VERSION 5.8 ;
BUSBITCHARS "[]" ;
DIVIDERCHAR "/" ;
UNITS
    DATABASE MICRONS 1000 ;
END UNITS

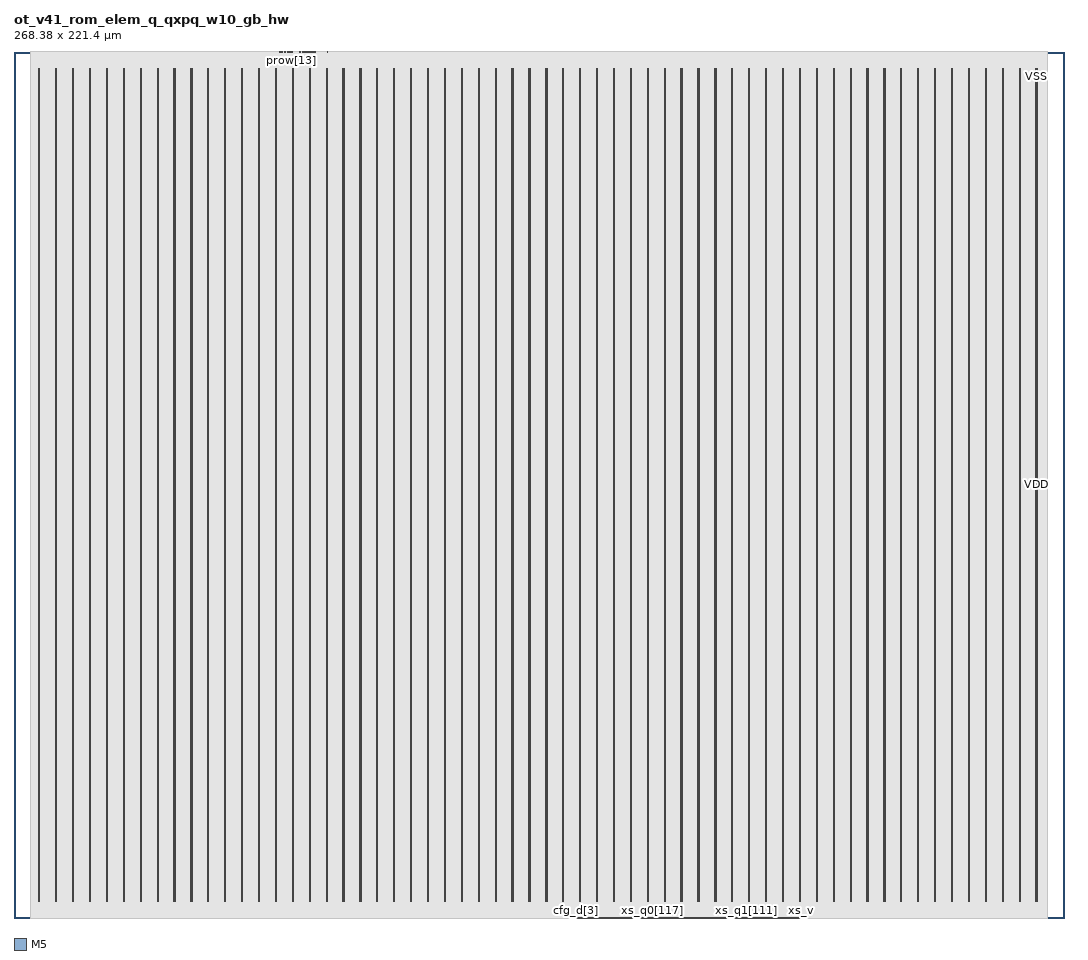
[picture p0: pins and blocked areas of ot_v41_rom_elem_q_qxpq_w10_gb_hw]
MACRO ot_v41_rom_elem_q_qxpq_w10_gb_hw
  FOREIGN ot_v41_rom_elem_q_qxpq_w10_gb_hw 0 0 ;
  CLASS BLOCK ;
  SIZE 268.38 BY 221.4 ;
  PIN bank_free
    DIRECTION OUTPUT ;
    USE SIGNAL ;
    PORT
      LAYER M5 ;
        RECT  142.752 0 142.776 0.084 ;
    END
  END bank_free
  PIN busy
    DIRECTION OUTPUT ;
    USE SIGNAL ;
    PORT
      LAYER M5 ;
        RECT  67.872 221.316 67.896 221.4 ;
    END
  END busy
  PIN cfg_a[0]
    DIRECTION INPUT ;
    USE SIGNAL ;
    PORT
      LAYER M5 ;
        RECT  142.848 0 142.872 0.084 ;
    END
  END cfg_a[0]
  PIN cfg_a[1]
    DIRECTION INPUT ;
    USE SIGNAL ;
    PORT
      LAYER M5 ;
        RECT  142.944 0 142.968 0.084 ;
    END
  END cfg_a[1]
  PIN cfg_a[2]
    DIRECTION INPUT ;
    USE SIGNAL ;
    PORT
      LAYER M5 ;
        RECT  143.04 0 143.064 0.084 ;
    END
  END cfg_a[2]
  PIN cfg_a[3]
    DIRECTION INPUT ;
    USE SIGNAL ;
    PORT
      LAYER M5 ;
        RECT  143.136 0 143.16 0.084 ;
    END
  END cfg_a[3]
  PIN cfg_a[4]
    DIRECTION INPUT ;
    USE SIGNAL ;
    PORT
      LAYER M5 ;
        RECT  143.232 0 143.256 0.084 ;
    END
  END cfg_a[4]
  PIN cfg_d[0]
    DIRECTION INPUT ;
    USE SIGNAL ;
    PORT
      LAYER M5 ;
        RECT  143.328 0 143.352 0.084 ;
    END
  END cfg_d[0]
  PIN cfg_d[10]
    DIRECTION INPUT ;
    USE SIGNAL ;
    PORT
      LAYER M5 ;
        RECT  144.288 0 144.312 0.084 ;
    END
  END cfg_d[10]
  PIN cfg_d[11]
    DIRECTION INPUT ;
    USE SIGNAL ;
    PORT
      LAYER M5 ;
        RECT  144.384 0 144.408 0.084 ;
    END
  END cfg_d[11]
  PIN cfg_d[12]
    DIRECTION INPUT ;
    USE SIGNAL ;
    PORT
      LAYER M5 ;
        RECT  144.48 0 144.504 0.084 ;
    END
  END cfg_d[12]
  PIN cfg_d[13]
    DIRECTION INPUT ;
    USE SIGNAL ;
    PORT
      LAYER M5 ;
        RECT  144.576 0 144.6 0.084 ;
    END
  END cfg_d[13]
  PIN cfg_d[14]
    DIRECTION INPUT ;
    USE SIGNAL ;
    PORT
      LAYER M5 ;
        RECT  144.672 0 144.696 0.084 ;
    END
  END cfg_d[14]
  PIN cfg_d[15]
    DIRECTION INPUT ;
    USE SIGNAL ;
    PORT
      LAYER M5 ;
        RECT  144.768 0 144.792 0.084 ;
    END
  END cfg_d[15]
  PIN cfg_d[16]
    DIRECTION INPUT ;
    USE SIGNAL ;
    PORT
      LAYER M5 ;
        RECT  144.864 0 144.888 0.084 ;
    END
  END cfg_d[16]
  PIN cfg_d[17]
    DIRECTION INPUT ;
    USE SIGNAL ;
    PORT
      LAYER M5 ;
        RECT  144.96 0 144.984 0.084 ;
    END
  END cfg_d[17]
  PIN cfg_d[18]
    DIRECTION INPUT ;
    USE SIGNAL ;
    PORT
      LAYER M5 ;
        RECT  145.056 0 145.08 0.084 ;
    END
  END cfg_d[18]
  PIN cfg_d[19]
    DIRECTION INPUT ;
    USE SIGNAL ;
    PORT
      LAYER M5 ;
        RECT  145.152 0 145.176 0.084 ;
    END
  END cfg_d[19]
  PIN cfg_d[1]
    DIRECTION INPUT ;
    USE SIGNAL ;
    PORT
      LAYER M5 ;
        RECT  143.424 0 143.448 0.084 ;
    END
  END cfg_d[1]
  PIN cfg_d[20]
    DIRECTION INPUT ;
    USE SIGNAL ;
    PORT
      LAYER M5 ;
        RECT  145.248 0 145.272 0.084 ;
    END
  END cfg_d[20]
  PIN cfg_d[21]
    DIRECTION INPUT ;
    USE SIGNAL ;
    PORT
      LAYER M5 ;
        RECT  145.344 0 145.368 0.084 ;
    END
  END cfg_d[21]
  PIN cfg_d[22]
    DIRECTION INPUT ;
    USE SIGNAL ;
    PORT
      LAYER M5 ;
        RECT  145.44 0 145.464 0.084 ;
    END
  END cfg_d[22]
  PIN cfg_d[23]
    DIRECTION INPUT ;
    USE SIGNAL ;
    PORT
      LAYER M5 ;
        RECT  145.536 0 145.56 0.084 ;
    END
  END cfg_d[23]
  PIN cfg_d[24]
    DIRECTION INPUT ;
    USE SIGNAL ;
    PORT
      LAYER M5 ;
        RECT  145.632 0 145.656 0.084 ;
    END
  END cfg_d[24]
  PIN cfg_d[25]
    DIRECTION INPUT ;
    USE SIGNAL ;
    PORT
      LAYER M5 ;
        RECT  145.728 0 145.752 0.084 ;
    END
  END cfg_d[25]
  PIN cfg_d[26]
    DIRECTION INPUT ;
    USE SIGNAL ;
    PORT
      LAYER M5 ;
        RECT  145.824 0 145.848 0.084 ;
    END
  END cfg_d[26]
  PIN cfg_d[27]
    DIRECTION INPUT ;
    USE SIGNAL ;
    PORT
      LAYER M5 ;
        RECT  145.92 0 145.944 0.084 ;
    END
  END cfg_d[27]
  PIN cfg_d[28]
    DIRECTION INPUT ;
    USE SIGNAL ;
    PORT
      LAYER M5 ;
        RECT  146.016 0 146.04 0.084 ;
    END
  END cfg_d[28]
  PIN cfg_d[29]
    DIRECTION INPUT ;
    USE SIGNAL ;
    PORT
      LAYER M5 ;
        RECT  146.112 0 146.136 0.084 ;
    END
  END cfg_d[29]
  PIN cfg_d[2]
    DIRECTION INPUT ;
    USE SIGNAL ;
    PORT
      LAYER M5 ;
        RECT  143.52 0 143.544 0.084 ;
    END
  END cfg_d[2]
  PIN cfg_d[30]
    DIRECTION INPUT ;
    USE SIGNAL ;
    PORT
      LAYER M5 ;
        RECT  146.208 0 146.232 0.084 ;
    END
  END cfg_d[30]
  PIN cfg_d[31]
    DIRECTION INPUT ;
    USE SIGNAL ;
    PORT
      LAYER M5 ;
        RECT  146.304 0 146.328 0.084 ;
    END
  END cfg_d[31]
  PIN cfg_d[32]
    DIRECTION INPUT ;
    USE SIGNAL ;
    PORT
      LAYER M5 ;
        RECT  146.4 0 146.424 0.084 ;
    END
  END cfg_d[32]
  PIN cfg_d[33]
    DIRECTION INPUT ;
    USE SIGNAL ;
    PORT
      LAYER M5 ;
        RECT  146.496 0 146.52 0.084 ;
    END
  END cfg_d[33]
  PIN cfg_d[34]
    DIRECTION INPUT ;
    USE SIGNAL ;
    PORT
      LAYER M5 ;
        RECT  146.592 0 146.616 0.084 ;
    END
  END cfg_d[34]
  PIN cfg_d[35]
    DIRECTION INPUT ;
    USE SIGNAL ;
    PORT
      LAYER M5 ;
        RECT  146.688 0 146.712 0.084 ;
    END
  END cfg_d[35]
  PIN cfg_d[36]
    DIRECTION INPUT ;
    USE SIGNAL ;
    PORT
      LAYER M5 ;
        RECT  146.784 0 146.808 0.084 ;
    END
  END cfg_d[36]
  PIN cfg_d[37]
    DIRECTION INPUT ;
    USE SIGNAL ;
    PORT
      LAYER M5 ;
        RECT  146.88 0 146.904 0.084 ;
    END
  END cfg_d[37]
  PIN cfg_d[38]
    DIRECTION INPUT ;
    USE SIGNAL ;
    PORT
      LAYER M5 ;
        RECT  146.976 0 147 0.084 ;
    END
  END cfg_d[38]
  PIN cfg_d[39]
    DIRECTION INPUT ;
    USE SIGNAL ;
    PORT
      LAYER M5 ;
        RECT  147.072 0 147.096 0.084 ;
    END
  END cfg_d[39]
  PIN cfg_d[3]
    DIRECTION INPUT ;
    USE SIGNAL ;
    PORT
      LAYER M5 ;
        RECT  143.616 0 143.64 0.084 ;
    END
  END cfg_d[3]
  PIN cfg_d[40]
    DIRECTION INPUT ;
    USE SIGNAL ;
    PORT
      LAYER M5 ;
        RECT  147.168 0 147.192 0.084 ;
    END
  END cfg_d[40]
  PIN cfg_d[41]
    DIRECTION INPUT ;
    USE SIGNAL ;
    PORT
      LAYER M5 ;
        RECT  147.264 0 147.288 0.084 ;
    END
  END cfg_d[41]
  PIN cfg_d[42]
    DIRECTION INPUT ;
    USE SIGNAL ;
    PORT
      LAYER M5 ;
        RECT  147.36 0 147.384 0.084 ;
    END
  END cfg_d[42]
  PIN cfg_d[43]
    DIRECTION INPUT ;
    USE SIGNAL ;
    PORT
      LAYER M5 ;
        RECT  147.456 0 147.48 0.084 ;
    END
  END cfg_d[43]
  PIN cfg_d[44]
    DIRECTION INPUT ;
    USE SIGNAL ;
    PORT
      LAYER M5 ;
        RECT  147.552 0 147.576 0.084 ;
    END
  END cfg_d[44]
  PIN cfg_d[45]
    DIRECTION INPUT ;
    USE SIGNAL ;
    PORT
      LAYER M5 ;
        RECT  147.648 0 147.672 0.084 ;
    END
  END cfg_d[45]
  PIN cfg_d[46]
    DIRECTION INPUT ;
    USE SIGNAL ;
    PORT
      LAYER M5 ;
        RECT  147.744 0 147.768 0.084 ;
    END
  END cfg_d[46]
  PIN cfg_d[47]
    DIRECTION INPUT ;
    USE SIGNAL ;
    PORT
      LAYER M5 ;
        RECT  147.84 0 147.864 0.084 ;
    END
  END cfg_d[47]
  PIN cfg_d[4]
    DIRECTION INPUT ;
    USE SIGNAL ;
    PORT
      LAYER M5 ;
        RECT  143.712 0 143.736 0.084 ;
    END
  END cfg_d[4]
  PIN cfg_d[5]
    DIRECTION INPUT ;
    USE SIGNAL ;
    PORT
      LAYER M5 ;
        RECT  143.808 0 143.832 0.084 ;
    END
  END cfg_d[5]
  PIN cfg_d[6]
    DIRECTION INPUT ;
    USE SIGNAL ;
    PORT
      LAYER M5 ;
        RECT  143.904 0 143.928 0.084 ;
    END
  END cfg_d[6]
  PIN cfg_d[7]
    DIRECTION INPUT ;
    USE SIGNAL ;
    PORT
      LAYER M5 ;
        RECT  144 0 144.024 0.084 ;
    END
  END cfg_d[7]
  PIN cfg_d[8]
    DIRECTION INPUT ;
    USE SIGNAL ;
    PORT
      LAYER M5 ;
        RECT  144.096 0 144.12 0.084 ;
    END
  END cfg_d[8]
  PIN cfg_d[9]
    DIRECTION INPUT ;
    USE SIGNAL ;
    PORT
      LAYER M5 ;
        RECT  144.192 0 144.216 0.084 ;
    END
  END cfg_d[9]
  PIN cfg_v
    DIRECTION INPUT ;
    USE SIGNAL ;
    PORT
      LAYER M5 ;
        RECT  147.936 0 147.96 0.084 ;
    END
  END cfg_v
  PIN clk
    DIRECTION INPUT ;
    USE SIGNAL ;
    PORT
      LAYER M5 ;
        RECT  148.032 0 148.056 0.084 ;
    END
  END clk
  PIN fault
    DIRECTION OUTPUT ;
    USE SIGNAL ;
    PORT
      LAYER M5 ;
        RECT  67.968 221.316 67.992 221.4 ;
    END
  END fault
  PIN go
    DIRECTION INPUT ;
    USE SIGNAL ;
    PORT
      LAYER M5 ;
        RECT  148.128 0 148.152 0.084 ;
    END
  END go
  PIN go_tag[0]
    DIRECTION INPUT ;
    USE SIGNAL ;
    PORT
      LAYER M5 ;
        RECT  148.224 0 148.248 0.084 ;
    END
  END go_tag[0]
  PIN go_tag[1]
    DIRECTION INPUT ;
    USE SIGNAL ;
    PORT
      LAYER M5 ;
        RECT  148.32 0 148.344 0.084 ;
    END
  END go_tag[1]
  PIN perr
    DIRECTION OUTPUT ;
    USE SIGNAL ;
    PORT
      LAYER M5 ;
        RECT  68.064 221.316 68.088 221.4 ;
    END
  END perr
  PIN pnseg[0]
    DIRECTION OUTPUT ;
    USE SIGNAL ;
    PORT
      LAYER M5 ;
        RECT  68.256 221.316 68.28 221.4 ;
    END
  END pnseg[0]
  PIN pnseg[1]
    DIRECTION OUTPUT ;
    USE SIGNAL ;
    PORT
      LAYER M5 ;
        RECT  68.352 221.316 68.376 221.4 ;
    END
  END pnseg[1]
  PIN pnseg[2]
    DIRECTION OUTPUT ;
    USE SIGNAL ;
    PORT
      LAYER M5 ;
        RECT  68.448 221.316 68.472 221.4 ;
    END
  END pnseg[2]
  PIN pnseg[3]
    DIRECTION OUTPUT ;
    USE SIGNAL ;
    PORT
      LAYER M5 ;
        RECT  68.544 221.316 68.568 221.4 ;
    END
  END pnseg[3]
  PIN pnseg[4]
    DIRECTION OUTPUT ;
    USE SIGNAL ;
    PORT
      LAYER M5 ;
        RECT  68.64 221.316 68.664 221.4 ;
    END
  END pnseg[4]
  PIN ppos[0]
    DIRECTION OUTPUT ;
    USE SIGNAL ;
    PORT
      LAYER M5 ;
        RECT  69.216 221.316 69.24 221.4 ;
    END
  END ppos[0]
  PIN ppos[1]
    DIRECTION OUTPUT ;
    USE SIGNAL ;
    PORT
      LAYER M5 ;
        RECT  69.312 221.316 69.336 221.4 ;
    END
  END ppos[1]
  PIN ppos[2]
    DIRECTION OUTPUT ;
    USE SIGNAL ;
    PORT
      LAYER M5 ;
        RECT  69.408 221.316 69.432 221.4 ;
    END
  END ppos[2]
  PIN prow[0]
    DIRECTION OUTPUT ;
    USE SIGNAL ;
    PORT
      LAYER M5 ;
        RECT  69.792 221.316 69.816 221.4 ;
    END
  END prow[0]
  PIN prow[10]
    DIRECTION OUTPUT ;
    USE SIGNAL ;
    PORT
      LAYER M5 ;
        RECT  70.752 221.316 70.776 221.4 ;
    END
  END prow[10]
  PIN prow[11]
    DIRECTION OUTPUT ;
    USE SIGNAL ;
    PORT
      LAYER M5 ;
        RECT  70.848 221.316 70.872 221.4 ;
    END
  END prow[11]
  PIN prow[12]
    DIRECTION OUTPUT ;
    USE SIGNAL ;
    PORT
      LAYER M5 ;
        RECT  70.944 221.316 70.968 221.4 ;
    END
  END prow[12]
  PIN prow[13]
    DIRECTION OUTPUT ;
    USE SIGNAL ;
    PORT
      LAYER M5 ;
        RECT  71.04 221.316 71.064 221.4 ;
    END
  END prow[13]
  PIN prow[14]
    DIRECTION OUTPUT ;
    USE SIGNAL ;
    PORT
      LAYER M5 ;
        RECT  71.136 221.316 71.16 221.4 ;
    END
  END prow[14]
  PIN prow[15]
    DIRECTION OUTPUT ;
    USE SIGNAL ;
    PORT
      LAYER M5 ;
        RECT  71.232 221.316 71.256 221.4 ;
    END
  END prow[15]
  PIN prow[1]
    DIRECTION OUTPUT ;
    USE SIGNAL ;
    PORT
      LAYER M5 ;
        RECT  69.888 221.316 69.912 221.4 ;
    END
  END prow[1]
  PIN prow[2]
    DIRECTION OUTPUT ;
    USE SIGNAL ;
    PORT
      LAYER M5 ;
        RECT  69.984 221.316 70.008 221.4 ;
    END
  END prow[2]
  PIN prow[3]
    DIRECTION OUTPUT ;
    USE SIGNAL ;
    PORT
      LAYER M5 ;
        RECT  70.08 221.316 70.104 221.4 ;
    END
  END prow[3]
  PIN prow[4]
    DIRECTION OUTPUT ;
    USE SIGNAL ;
    PORT
      LAYER M5 ;
        RECT  70.176 221.316 70.2 221.4 ;
    END
  END prow[4]
  PIN prow[5]
    DIRECTION OUTPUT ;
    USE SIGNAL ;
    PORT
      LAYER M5 ;
        RECT  70.272 221.316 70.296 221.4 ;
    END
  END prow[5]
  PIN prow[6]
    DIRECTION OUTPUT ;
    USE SIGNAL ;
    PORT
      LAYER M5 ;
        RECT  70.368 221.316 70.392 221.4 ;
    END
  END prow[6]
  PIN prow[7]
    DIRECTION OUTPUT ;
    USE SIGNAL ;
    PORT
      LAYER M5 ;
        RECT  70.464 221.316 70.488 221.4 ;
    END
  END prow[7]
  PIN prow[8]
    DIRECTION OUTPUT ;
    USE SIGNAL ;
    PORT
      LAYER M5 ;
        RECT  70.56 221.316 70.584 221.4 ;
    END
  END prow[8]
  PIN prow[9]
    DIRECTION OUTPUT ;
    USE SIGNAL ;
    PORT
      LAYER M5 ;
        RECT  70.656 221.316 70.68 221.4 ;
    END
  END prow[9]
  PIN pseg[0]
    DIRECTION OUTPUT ;
    USE SIGNAL ;
    PORT
      LAYER M5 ;
        RECT  72.864 221.316 72.888 221.4 ;
    END
  END pseg[0]
  PIN pseg[1]
    DIRECTION OUTPUT ;
    USE SIGNAL ;
    PORT
      LAYER M5 ;
        RECT  72.96 221.316 72.984 221.4 ;
    END
  END pseg[1]
  PIN pseg[2]
    DIRECTION OUTPUT ;
    USE SIGNAL ;
    PORT
      LAYER M5 ;
        RECT  73.056 221.316 73.08 221.4 ;
    END
  END pseg[2]
  PIN pseg[3]
    DIRECTION OUTPUT ;
    USE SIGNAL ;
    PORT
      LAYER M5 ;
        RECT  73.152 221.316 73.176 221.4 ;
    END
  END pseg[3]
  PIN pseg[4]
    DIRECTION OUTPUT ;
    USE SIGNAL ;
    PORT
      LAYER M5 ;
        RECT  73.248 221.316 73.272 221.4 ;
    END
  END pseg[4]
  PIN pv
    DIRECTION OUTPUT ;
    USE SIGNAL ;
    PORT
      LAYER M5 ;
        RECT  73.824 221.316 73.848 221.4 ;
    END
  END pv
  PIN pval[0]
    DIRECTION OUTPUT ;
    USE SIGNAL ;
    PORT
      LAYER M5 ;
        RECT  74.016 221.316 74.04 221.4 ;
    END
  END pval[0]
  PIN pval[10]
    DIRECTION OUTPUT ;
    USE SIGNAL ;
    PORT
      LAYER M5 ;
        RECT  74.976 221.316 75 221.4 ;
    END
  END pval[10]
  PIN pval[11]
    DIRECTION OUTPUT ;
    USE SIGNAL ;
    PORT
      LAYER M5 ;
        RECT  75.072 221.316 75.096 221.4 ;
    END
  END pval[11]
  PIN pval[12]
    DIRECTION OUTPUT ;
    USE SIGNAL ;
    PORT
      LAYER M5 ;
        RECT  75.168 221.316 75.192 221.4 ;
    END
  END pval[12]
  PIN pval[13]
    DIRECTION OUTPUT ;
    USE SIGNAL ;
    PORT
      LAYER M5 ;
        RECT  75.264 221.316 75.288 221.4 ;
    END
  END pval[13]
  PIN pval[14]
    DIRECTION OUTPUT ;
    USE SIGNAL ;
    PORT
      LAYER M5 ;
        RECT  75.36 221.316 75.384 221.4 ;
    END
  END pval[14]
  PIN pval[15]
    DIRECTION OUTPUT ;
    USE SIGNAL ;
    PORT
      LAYER M5 ;
        RECT  75.456 221.316 75.48 221.4 ;
    END
  END pval[15]
  PIN pval[16]
    DIRECTION OUTPUT ;
    USE SIGNAL ;
    PORT
      LAYER M5 ;
        RECT  75.552 221.316 75.576 221.4 ;
    END
  END pval[16]
  PIN pval[17]
    DIRECTION OUTPUT ;
    USE SIGNAL ;
    PORT
      LAYER M5 ;
        RECT  75.648 221.316 75.672 221.4 ;
    END
  END pval[17]
  PIN pval[18]
    DIRECTION OUTPUT ;
    USE SIGNAL ;
    PORT
      LAYER M5 ;
        RECT  75.744 221.316 75.768 221.4 ;
    END
  END pval[18]
  PIN pval[19]
    DIRECTION OUTPUT ;
    USE SIGNAL ;
    PORT
      LAYER M5 ;
        RECT  75.84 221.316 75.864 221.4 ;
    END
  END pval[19]
  PIN pval[1]
    DIRECTION OUTPUT ;
    USE SIGNAL ;
    PORT
      LAYER M5 ;
        RECT  74.112 221.316 74.136 221.4 ;
    END
  END pval[1]
  PIN pval[20]
    DIRECTION OUTPUT ;
    USE SIGNAL ;
    PORT
      LAYER M5 ;
        RECT  75.936 221.316 75.96 221.4 ;
    END
  END pval[20]
  PIN pval[21]
    DIRECTION OUTPUT ;
    USE SIGNAL ;
    PORT
      LAYER M5 ;
        RECT  76.032 221.316 76.056 221.4 ;
    END
  END pval[21]
  PIN pval[22]
    DIRECTION OUTPUT ;
    USE SIGNAL ;
    PORT
      LAYER M5 ;
        RECT  76.128 221.316 76.152 221.4 ;
    END
  END pval[22]
  PIN pval[23]
    DIRECTION OUTPUT ;
    USE SIGNAL ;
    PORT
      LAYER M5 ;
        RECT  76.224 221.316 76.248 221.4 ;
    END
  END pval[23]
  PIN pval[24]
    DIRECTION OUTPUT ;
    USE SIGNAL ;
    PORT
      LAYER M5 ;
        RECT  76.32 221.316 76.344 221.4 ;
    END
  END pval[24]
  PIN pval[25]
    DIRECTION OUTPUT ;
    USE SIGNAL ;
    PORT
      LAYER M5 ;
        RECT  76.416 221.316 76.44 221.4 ;
    END
  END pval[25]
  PIN pval[26]
    DIRECTION OUTPUT ;
    USE SIGNAL ;
    PORT
      LAYER M5 ;
        RECT  76.512 221.316 76.536 221.4 ;
    END
  END pval[26]
  PIN pval[27]
    DIRECTION OUTPUT ;
    USE SIGNAL ;
    PORT
      LAYER M5 ;
        RECT  76.608 221.316 76.632 221.4 ;
    END
  END pval[27]
  PIN pval[28]
    DIRECTION OUTPUT ;
    USE SIGNAL ;
    PORT
      LAYER M5 ;
        RECT  76.704 221.316 76.728 221.4 ;
    END
  END pval[28]
  PIN pval[29]
    DIRECTION OUTPUT ;
    USE SIGNAL ;
    PORT
      LAYER M5 ;
        RECT  76.8 221.316 76.824 221.4 ;
    END
  END pval[29]
  PIN pval[2]
    DIRECTION OUTPUT ;
    USE SIGNAL ;
    PORT
      LAYER M5 ;
        RECT  74.208 221.316 74.232 221.4 ;
    END
  END pval[2]
  PIN pval[30]
    DIRECTION OUTPUT ;
    USE SIGNAL ;
    PORT
      LAYER M5 ;
        RECT  76.896 221.316 76.92 221.4 ;
    END
  END pval[30]
  PIN pval[31]
    DIRECTION OUTPUT ;
    USE SIGNAL ;
    PORT
      LAYER M5 ;
        RECT  76.992 221.316 77.016 221.4 ;
    END
  END pval[31]
  PIN pval[3]
    DIRECTION OUTPUT ;
    USE SIGNAL ;
    PORT
      LAYER M5 ;
        RECT  74.304 221.316 74.328 221.4 ;
    END
  END pval[3]
  PIN pval[4]
    DIRECTION OUTPUT ;
    USE SIGNAL ;
    PORT
      LAYER M5 ;
        RECT  74.4 221.316 74.424 221.4 ;
    END
  END pval[4]
  PIN pval[5]
    DIRECTION OUTPUT ;
    USE SIGNAL ;
    PORT
      LAYER M5 ;
        RECT  74.496 221.316 74.52 221.4 ;
    END
  END pval[5]
  PIN pval[6]
    DIRECTION OUTPUT ;
    USE SIGNAL ;
    PORT
      LAYER M5 ;
        RECT  74.592 221.316 74.616 221.4 ;
    END
  END pval[6]
  PIN pval[7]
    DIRECTION OUTPUT ;
    USE SIGNAL ;
    PORT
      LAYER M5 ;
        RECT  74.688 221.316 74.712 221.4 ;
    END
  END pval[7]
  PIN pval[8]
    DIRECTION OUTPUT ;
    USE SIGNAL ;
    PORT
      LAYER M5 ;
        RECT  74.784 221.316 74.808 221.4 ;
    END
  END pval[8]
  PIN pval[9]
    DIRECTION OUTPUT ;
    USE SIGNAL ;
    PORT
      LAYER M5 ;
        RECT  74.88 221.316 74.904 221.4 ;
    END
  END pval[9]
  PIN rst_n
    DIRECTION INPUT ;
    USE SIGNAL ;
    PORT
      LAYER M5 ;
        RECT  148.416 0 148.44 0.084 ;
    END
  END rst_n
  PIN sh_free
    DIRECTION OUTPUT ;
    USE SIGNAL ;
    PORT
      LAYER M5 ;
        RECT  148.512 0 148.536 0.084 ;
    END
  END sh_free
  PIN walking
    DIRECTION OUTPUT ;
    USE SIGNAL ;
    PORT
      LAYER M5 ;
        RECT  80.16 221.316 80.184 221.4 ;
    END
  END walking
  PIN xs_b[0]
    DIRECTION INPUT ;
    USE SIGNAL ;
    PORT
      LAYER M5 ;
        RECT  148.608 0 148.632 0.084 ;
    END
  END xs_b[0]
  PIN xs_b[1]
    DIRECTION INPUT ;
    USE SIGNAL ;
    PORT
      LAYER M5 ;
        RECT  148.704 0 148.728 0.084 ;
    END
  END xs_b[1]
  PIN xs_b[2]
    DIRECTION INPUT ;
    USE SIGNAL ;
    PORT
      LAYER M5 ;
        RECT  148.8 0 148.824 0.084 ;
    END
  END xs_b[2]
  PIN xs_e0[0]
    DIRECTION INPUT ;
    USE SIGNAL ;
    PORT
      LAYER M5 ;
        RECT  148.896 0 148.92 0.084 ;
    END
  END xs_e0[0]
  PIN xs_e0[1]
    DIRECTION INPUT ;
    USE SIGNAL ;
    PORT
      LAYER M5 ;
        RECT  148.992 0 149.016 0.084 ;
    END
  END xs_e0[1]
  PIN xs_e0[2]
    DIRECTION INPUT ;
    USE SIGNAL ;
    PORT
      LAYER M5 ;
        RECT  149.088 0 149.112 0.084 ;
    END
  END xs_e0[2]
  PIN xs_e0[3]
    DIRECTION INPUT ;
    USE SIGNAL ;
    PORT
      LAYER M5 ;
        RECT  149.184 0 149.208 0.084 ;
    END
  END xs_e0[3]
  PIN xs_e0[4]
    DIRECTION INPUT ;
    USE SIGNAL ;
    PORT
      LAYER M5 ;
        RECT  149.28 0 149.304 0.084 ;
    END
  END xs_e0[4]
  PIN xs_e0[5]
    DIRECTION INPUT ;
    USE SIGNAL ;
    PORT
      LAYER M5 ;
        RECT  149.376 0 149.4 0.084 ;
    END
  END xs_e0[5]
  PIN xs_e0[6]
    DIRECTION INPUT ;
    USE SIGNAL ;
    PORT
      LAYER M5 ;
        RECT  149.472 0 149.496 0.084 ;
    END
  END xs_e0[6]
  PIN xs_e0[7]
    DIRECTION INPUT ;
    USE SIGNAL ;
    PORT
      LAYER M5 ;
        RECT  149.568 0 149.592 0.084 ;
    END
  END xs_e0[7]
  PIN xs_e0[8]
    DIRECTION INPUT ;
    USE SIGNAL ;
    PORT
      LAYER M5 ;
        RECT  149.664 0 149.688 0.084 ;
    END
  END xs_e0[8]
  PIN xs_e0[9]
    DIRECTION INPUT ;
    USE SIGNAL ;
    PORT
      LAYER M5 ;
        RECT  149.76 0 149.784 0.084 ;
    END
  END xs_e0[9]
  PIN xs_e1[0]
    DIRECTION INPUT ;
    USE SIGNAL ;
    PORT
      LAYER M5 ;
        RECT  149.856 0 149.88 0.084 ;
    END
  END xs_e1[0]
  PIN xs_e1[1]
    DIRECTION INPUT ;
    USE SIGNAL ;
    PORT
      LAYER M5 ;
        RECT  149.952 0 149.976 0.084 ;
    END
  END xs_e1[1]
  PIN xs_e1[2]
    DIRECTION INPUT ;
    USE SIGNAL ;
    PORT
      LAYER M5 ;
        RECT  150.048 0 150.072 0.084 ;
    END
  END xs_e1[2]
  PIN xs_e1[3]
    DIRECTION INPUT ;
    USE SIGNAL ;
    PORT
      LAYER M5 ;
        RECT  150.144 0 150.168 0.084 ;
    END
  END xs_e1[3]
  PIN xs_e1[4]
    DIRECTION INPUT ;
    USE SIGNAL ;
    PORT
      LAYER M5 ;
        RECT  150.24 0 150.264 0.084 ;
    END
  END xs_e1[4]
  PIN xs_e1[5]
    DIRECTION INPUT ;
    USE SIGNAL ;
    PORT
      LAYER M5 ;
        RECT  150.336 0 150.36 0.084 ;
    END
  END xs_e1[5]
  PIN xs_e1[6]
    DIRECTION INPUT ;
    USE SIGNAL ;
    PORT
      LAYER M5 ;
        RECT  150.432 0 150.456 0.084 ;
    END
  END xs_e1[6]
  PIN xs_e1[7]
    DIRECTION INPUT ;
    USE SIGNAL ;
    PORT
      LAYER M5 ;
        RECT  150.528 0 150.552 0.084 ;
    END
  END xs_e1[7]
  PIN xs_e1[8]
    DIRECTION INPUT ;
    USE SIGNAL ;
    PORT
      LAYER M5 ;
        RECT  150.624 0 150.648 0.084 ;
    END
  END xs_e1[8]
  PIN xs_e1[9]
    DIRECTION INPUT ;
    USE SIGNAL ;
    PORT
      LAYER M5 ;
        RECT  150.72 0 150.744 0.084 ;
    END
  END xs_e1[9]
  PIN xs_p[0]
    DIRECTION INPUT ;
    USE SIGNAL ;
    PORT
      LAYER M5 ;
        RECT  150.816 0 150.84 0.084 ;
    END
  END xs_p[0]
  PIN xs_p[1]
    DIRECTION INPUT ;
    USE SIGNAL ;
    PORT
      LAYER M5 ;
        RECT  150.912 0 150.936 0.084 ;
    END
  END xs_p[1]
  PIN xs_p[2]
    DIRECTION INPUT ;
    USE SIGNAL ;
    PORT
      LAYER M5 ;
        RECT  151.008 0 151.032 0.084 ;
    END
  END xs_p[2]
  PIN xs_p[3]
    DIRECTION INPUT ;
    USE SIGNAL ;
    PORT
      LAYER M5 ;
        RECT  151.104 0 151.128 0.084 ;
    END
  END xs_p[3]
  PIN xs_p[4]
    DIRECTION INPUT ;
    USE SIGNAL ;
    PORT
      LAYER M5 ;
        RECT  151.2 0 151.224 0.084 ;
    END
  END xs_p[4]
  PIN xs_p[5]
    DIRECTION INPUT ;
    USE SIGNAL ;
    PORT
      LAYER M5 ;
        RECT  151.296 0 151.32 0.084 ;
    END
  END xs_p[5]
  PIN xs_p[6]
    DIRECTION INPUT ;
    USE SIGNAL ;
    PORT
      LAYER M5 ;
        RECT  151.392 0 151.416 0.084 ;
    END
  END xs_p[6]
  PIN xs_p[7]
    DIRECTION INPUT ;
    USE SIGNAL ;
    PORT
      LAYER M5 ;
        RECT  151.488 0 151.512 0.084 ;
    END
  END xs_p[7]
  PIN xs_pos[0]
    DIRECTION INPUT ;
    USE SIGNAL ;
    PORT
      LAYER M5 ;
        RECT  151.584 0 151.608 0.084 ;
    END
  END xs_pos[0]
  PIN xs_pos[1]
    DIRECTION INPUT ;
    USE SIGNAL ;
    PORT
      LAYER M5 ;
        RECT  151.68 0 151.704 0.084 ;
    END
  END xs_pos[1]
  PIN xs_pos[2]
    DIRECTION INPUT ;
    USE SIGNAL ;
    PORT
      LAYER M5 ;
        RECT  151.776 0 151.8 0.084 ;
    END
  END xs_pos[2]
  PIN xs_q0[0]
    DIRECTION INPUT ;
    USE SIGNAL ;
    PORT
      LAYER M5 ;
        RECT  151.872 0 151.896 0.084 ;
    END
  END xs_q0[0]
  PIN xs_q0[100]
    DIRECTION INPUT ;
    USE SIGNAL ;
    PORT
      LAYER M5 ;
        RECT  161.472 0 161.496 0.084 ;
    END
  END xs_q0[100]
  PIN xs_q0[101]
    DIRECTION INPUT ;
    USE SIGNAL ;
    PORT
      LAYER M5 ;
        RECT  161.568 0 161.592 0.084 ;
    END
  END xs_q0[101]
  PIN xs_q0[102]
    DIRECTION INPUT ;
    USE SIGNAL ;
    PORT
      LAYER M5 ;
        RECT  161.664 0 161.688 0.084 ;
    END
  END xs_q0[102]
  PIN xs_q0[103]
    DIRECTION INPUT ;
    USE SIGNAL ;
    PORT
      LAYER M5 ;
        RECT  161.76 0 161.784 0.084 ;
    END
  END xs_q0[103]
  PIN xs_q0[104]
    DIRECTION INPUT ;
    USE SIGNAL ;
    PORT
      LAYER M5 ;
        RECT  161.856 0 161.88 0.084 ;
    END
  END xs_q0[104]
  PIN xs_q0[105]
    DIRECTION INPUT ;
    USE SIGNAL ;
    PORT
      LAYER M5 ;
        RECT  161.952 0 161.976 0.084 ;
    END
  END xs_q0[105]
  PIN xs_q0[106]
    DIRECTION INPUT ;
    USE SIGNAL ;
    PORT
      LAYER M5 ;
        RECT  162.048 0 162.072 0.084 ;
    END
  END xs_q0[106]
  PIN xs_q0[107]
    DIRECTION INPUT ;
    USE SIGNAL ;
    PORT
      LAYER M5 ;
        RECT  162.144 0 162.168 0.084 ;
    END
  END xs_q0[107]
  PIN xs_q0[108]
    DIRECTION INPUT ;
    USE SIGNAL ;
    PORT
      LAYER M5 ;
        RECT  162.24 0 162.264 0.084 ;
    END
  END xs_q0[108]
  PIN xs_q0[109]
    DIRECTION INPUT ;
    USE SIGNAL ;
    PORT
      LAYER M5 ;
        RECT  162.336 0 162.36 0.084 ;
    END
  END xs_q0[109]
  PIN xs_q0[10]
    DIRECTION INPUT ;
    USE SIGNAL ;
    PORT
      LAYER M5 ;
        RECT  152.832 0 152.856 0.084 ;
    END
  END xs_q0[10]
  PIN xs_q0[110]
    DIRECTION INPUT ;
    USE SIGNAL ;
    PORT
      LAYER M5 ;
        RECT  162.432 0 162.456 0.084 ;
    END
  END xs_q0[110]
  PIN xs_q0[111]
    DIRECTION INPUT ;
    USE SIGNAL ;
    PORT
      LAYER M5 ;
        RECT  162.528 0 162.552 0.084 ;
    END
  END xs_q0[111]
  PIN xs_q0[112]
    DIRECTION INPUT ;
    USE SIGNAL ;
    PORT
      LAYER M5 ;
        RECT  162.624 0 162.648 0.084 ;
    END
  END xs_q0[112]
  PIN xs_q0[113]
    DIRECTION INPUT ;
    USE SIGNAL ;
    PORT
      LAYER M5 ;
        RECT  162.72 0 162.744 0.084 ;
    END
  END xs_q0[113]
  PIN xs_q0[114]
    DIRECTION INPUT ;
    USE SIGNAL ;
    PORT
      LAYER M5 ;
        RECT  162.816 0 162.84 0.084 ;
    END
  END xs_q0[114]
  PIN xs_q0[115]
    DIRECTION INPUT ;
    USE SIGNAL ;
    PORT
      LAYER M5 ;
        RECT  162.912 0 162.936 0.084 ;
    END
  END xs_q0[115]
  PIN xs_q0[116]
    DIRECTION INPUT ;
    USE SIGNAL ;
    PORT
      LAYER M5 ;
        RECT  163.008 0 163.032 0.084 ;
    END
  END xs_q0[116]
  PIN xs_q0[117]
    DIRECTION INPUT ;
    USE SIGNAL ;
    PORT
      LAYER M5 ;
        RECT  163.104 0 163.128 0.084 ;
    END
  END xs_q0[117]
  PIN xs_q0[118]
    DIRECTION INPUT ;
    USE SIGNAL ;
    PORT
      LAYER M5 ;
        RECT  163.2 0 163.224 0.084 ;
    END
  END xs_q0[118]
  PIN xs_q0[119]
    DIRECTION INPUT ;
    USE SIGNAL ;
    PORT
      LAYER M5 ;
        RECT  163.296 0 163.32 0.084 ;
    END
  END xs_q0[119]
  PIN xs_q0[11]
    DIRECTION INPUT ;
    USE SIGNAL ;
    PORT
      LAYER M5 ;
        RECT  152.928 0 152.952 0.084 ;
    END
  END xs_q0[11]
  PIN xs_q0[120]
    DIRECTION INPUT ;
    USE SIGNAL ;
    PORT
      LAYER M5 ;
        RECT  163.392 0 163.416 0.084 ;
    END
  END xs_q0[120]
  PIN xs_q0[121]
    DIRECTION INPUT ;
    USE SIGNAL ;
    PORT
      LAYER M5 ;
        RECT  163.488 0 163.512 0.084 ;
    END
  END xs_q0[121]
  PIN xs_q0[122]
    DIRECTION INPUT ;
    USE SIGNAL ;
    PORT
      LAYER M5 ;
        RECT  163.584 0 163.608 0.084 ;
    END
  END xs_q0[122]
  PIN xs_q0[123]
    DIRECTION INPUT ;
    USE SIGNAL ;
    PORT
      LAYER M5 ;
        RECT  163.68 0 163.704 0.084 ;
    END
  END xs_q0[123]
  PIN xs_q0[124]
    DIRECTION INPUT ;
    USE SIGNAL ;
    PORT
      LAYER M5 ;
        RECT  163.776 0 163.8 0.084 ;
    END
  END xs_q0[124]
  PIN xs_q0[125]
    DIRECTION INPUT ;
    USE SIGNAL ;
    PORT
      LAYER M5 ;
        RECT  163.872 0 163.896 0.084 ;
    END
  END xs_q0[125]
  PIN xs_q0[126]
    DIRECTION INPUT ;
    USE SIGNAL ;
    PORT
      LAYER M5 ;
        RECT  163.968 0 163.992 0.084 ;
    END
  END xs_q0[126]
  PIN xs_q0[127]
    DIRECTION INPUT ;
    USE SIGNAL ;
    PORT
      LAYER M5 ;
        RECT  164.064 0 164.088 0.084 ;
    END
  END xs_q0[127]
  PIN xs_q0[128]
    DIRECTION INPUT ;
    USE SIGNAL ;
    PORT
      LAYER M5 ;
        RECT  164.16 0 164.184 0.084 ;
    END
  END xs_q0[128]
  PIN xs_q0[129]
    DIRECTION INPUT ;
    USE SIGNAL ;
    PORT
      LAYER M5 ;
        RECT  164.256 0 164.28 0.084 ;
    END
  END xs_q0[129]
  PIN xs_q0[12]
    DIRECTION INPUT ;
    USE SIGNAL ;
    PORT
      LAYER M5 ;
        RECT  153.024 0 153.048 0.084 ;
    END
  END xs_q0[12]
  PIN xs_q0[130]
    DIRECTION INPUT ;
    USE SIGNAL ;
    PORT
      LAYER M5 ;
        RECT  164.352 0 164.376 0.084 ;
    END
  END xs_q0[130]
  PIN xs_q0[131]
    DIRECTION INPUT ;
    USE SIGNAL ;
    PORT
      LAYER M5 ;
        RECT  164.448 0 164.472 0.084 ;
    END
  END xs_q0[131]
  PIN xs_q0[132]
    DIRECTION INPUT ;
    USE SIGNAL ;
    PORT
      LAYER M5 ;
        RECT  164.544 0 164.568 0.084 ;
    END
  END xs_q0[132]
  PIN xs_q0[133]
    DIRECTION INPUT ;
    USE SIGNAL ;
    PORT
      LAYER M5 ;
        RECT  164.64 0 164.664 0.084 ;
    END
  END xs_q0[133]
  PIN xs_q0[134]
    DIRECTION INPUT ;
    USE SIGNAL ;
    PORT
      LAYER M5 ;
        RECT  164.736 0 164.76 0.084 ;
    END
  END xs_q0[134]
  PIN xs_q0[135]
    DIRECTION INPUT ;
    USE SIGNAL ;
    PORT
      LAYER M5 ;
        RECT  164.832 0 164.856 0.084 ;
    END
  END xs_q0[135]
  PIN xs_q0[136]
    DIRECTION INPUT ;
    USE SIGNAL ;
    PORT
      LAYER M5 ;
        RECT  164.928 0 164.952 0.084 ;
    END
  END xs_q0[136]
  PIN xs_q0[137]
    DIRECTION INPUT ;
    USE SIGNAL ;
    PORT
      LAYER M5 ;
        RECT  165.024 0 165.048 0.084 ;
    END
  END xs_q0[137]
  PIN xs_q0[138]
    DIRECTION INPUT ;
    USE SIGNAL ;
    PORT
      LAYER M5 ;
        RECT  165.12 0 165.144 0.084 ;
    END
  END xs_q0[138]
  PIN xs_q0[139]
    DIRECTION INPUT ;
    USE SIGNAL ;
    PORT
      LAYER M5 ;
        RECT  165.216 0 165.24 0.084 ;
    END
  END xs_q0[139]
  PIN xs_q0[13]
    DIRECTION INPUT ;
    USE SIGNAL ;
    PORT
      LAYER M5 ;
        RECT  153.12 0 153.144 0.084 ;
    END
  END xs_q0[13]
  PIN xs_q0[140]
    DIRECTION INPUT ;
    USE SIGNAL ;
    PORT
      LAYER M5 ;
        RECT  165.312 0 165.336 0.084 ;
    END
  END xs_q0[140]
  PIN xs_q0[141]
    DIRECTION INPUT ;
    USE SIGNAL ;
    PORT
      LAYER M5 ;
        RECT  165.408 0 165.432 0.084 ;
    END
  END xs_q0[141]
  PIN xs_q0[142]
    DIRECTION INPUT ;
    USE SIGNAL ;
    PORT
      LAYER M5 ;
        RECT  165.504 0 165.528 0.084 ;
    END
  END xs_q0[142]
  PIN xs_q0[143]
    DIRECTION INPUT ;
    USE SIGNAL ;
    PORT
      LAYER M5 ;
        RECT  165.6 0 165.624 0.084 ;
    END
  END xs_q0[143]
  PIN xs_q0[144]
    DIRECTION INPUT ;
    USE SIGNAL ;
    PORT
      LAYER M5 ;
        RECT  165.696 0 165.72 0.084 ;
    END
  END xs_q0[144]
  PIN xs_q0[145]
    DIRECTION INPUT ;
    USE SIGNAL ;
    PORT
      LAYER M5 ;
        RECT  165.792 0 165.816 0.084 ;
    END
  END xs_q0[145]
  PIN xs_q0[146]
    DIRECTION INPUT ;
    USE SIGNAL ;
    PORT
      LAYER M5 ;
        RECT  165.888 0 165.912 0.084 ;
    END
  END xs_q0[146]
  PIN xs_q0[147]
    DIRECTION INPUT ;
    USE SIGNAL ;
    PORT
      LAYER M5 ;
        RECT  165.984 0 166.008 0.084 ;
    END
  END xs_q0[147]
  PIN xs_q0[148]
    DIRECTION INPUT ;
    USE SIGNAL ;
    PORT
      LAYER M5 ;
        RECT  166.08 0 166.104 0.084 ;
    END
  END xs_q0[148]
  PIN xs_q0[149]
    DIRECTION INPUT ;
    USE SIGNAL ;
    PORT
      LAYER M5 ;
        RECT  166.176 0 166.2 0.084 ;
    END
  END xs_q0[149]
  PIN xs_q0[14]
    DIRECTION INPUT ;
    USE SIGNAL ;
    PORT
      LAYER M5 ;
        RECT  153.216 0 153.24 0.084 ;
    END
  END xs_q0[14]
  PIN xs_q0[150]
    DIRECTION INPUT ;
    USE SIGNAL ;
    PORT
      LAYER M5 ;
        RECT  166.272 0 166.296 0.084 ;
    END
  END xs_q0[150]
  PIN xs_q0[151]
    DIRECTION INPUT ;
    USE SIGNAL ;
    PORT
      LAYER M5 ;
        RECT  166.368 0 166.392 0.084 ;
    END
  END xs_q0[151]
  PIN xs_q0[152]
    DIRECTION INPUT ;
    USE SIGNAL ;
    PORT
      LAYER M5 ;
        RECT  166.464 0 166.488 0.084 ;
    END
  END xs_q0[152]
  PIN xs_q0[153]
    DIRECTION INPUT ;
    USE SIGNAL ;
    PORT
      LAYER M5 ;
        RECT  166.56 0 166.584 0.084 ;
    END
  END xs_q0[153]
  PIN xs_q0[154]
    DIRECTION INPUT ;
    USE SIGNAL ;
    PORT
      LAYER M5 ;
        RECT  166.656 0 166.68 0.084 ;
    END
  END xs_q0[154]
  PIN xs_q0[155]
    DIRECTION INPUT ;
    USE SIGNAL ;
    PORT
      LAYER M5 ;
        RECT  166.752 0 166.776 0.084 ;
    END
  END xs_q0[155]
  PIN xs_q0[156]
    DIRECTION INPUT ;
    USE SIGNAL ;
    PORT
      LAYER M5 ;
        RECT  166.848 0 166.872 0.084 ;
    END
  END xs_q0[156]
  PIN xs_q0[157]
    DIRECTION INPUT ;
    USE SIGNAL ;
    PORT
      LAYER M5 ;
        RECT  166.944 0 166.968 0.084 ;
    END
  END xs_q0[157]
  PIN xs_q0[158]
    DIRECTION INPUT ;
    USE SIGNAL ;
    PORT
      LAYER M5 ;
        RECT  167.04 0 167.064 0.084 ;
    END
  END xs_q0[158]
  PIN xs_q0[159]
    DIRECTION INPUT ;
    USE SIGNAL ;
    PORT
      LAYER M5 ;
        RECT  167.136 0 167.16 0.084 ;
    END
  END xs_q0[159]
  PIN xs_q0[15]
    DIRECTION INPUT ;
    USE SIGNAL ;
    PORT
      LAYER M5 ;
        RECT  153.312 0 153.336 0.084 ;
    END
  END xs_q0[15]
  PIN xs_q0[160]
    DIRECTION INPUT ;
    USE SIGNAL ;
    PORT
      LAYER M5 ;
        RECT  167.232 0 167.256 0.084 ;
    END
  END xs_q0[160]
  PIN xs_q0[161]
    DIRECTION INPUT ;
    USE SIGNAL ;
    PORT
      LAYER M5 ;
        RECT  167.328 0 167.352 0.084 ;
    END
  END xs_q0[161]
  PIN xs_q0[162]
    DIRECTION INPUT ;
    USE SIGNAL ;
    PORT
      LAYER M5 ;
        RECT  167.424 0 167.448 0.084 ;
    END
  END xs_q0[162]
  PIN xs_q0[163]
    DIRECTION INPUT ;
    USE SIGNAL ;
    PORT
      LAYER M5 ;
        RECT  167.52 0 167.544 0.084 ;
    END
  END xs_q0[163]
  PIN xs_q0[164]
    DIRECTION INPUT ;
    USE SIGNAL ;
    PORT
      LAYER M5 ;
        RECT  167.616 0 167.64 0.084 ;
    END
  END xs_q0[164]
  PIN xs_q0[165]
    DIRECTION INPUT ;
    USE SIGNAL ;
    PORT
      LAYER M5 ;
        RECT  167.712 0 167.736 0.084 ;
    END
  END xs_q0[165]
  PIN xs_q0[166]
    DIRECTION INPUT ;
    USE SIGNAL ;
    PORT
      LAYER M5 ;
        RECT  167.808 0 167.832 0.084 ;
    END
  END xs_q0[166]
  PIN xs_q0[167]
    DIRECTION INPUT ;
    USE SIGNAL ;
    PORT
      LAYER M5 ;
        RECT  167.904 0 167.928 0.084 ;
    END
  END xs_q0[167]
  PIN xs_q0[168]
    DIRECTION INPUT ;
    USE SIGNAL ;
    PORT
      LAYER M5 ;
        RECT  168 0 168.024 0.084 ;
    END
  END xs_q0[168]
  PIN xs_q0[169]
    DIRECTION INPUT ;
    USE SIGNAL ;
    PORT
      LAYER M5 ;
        RECT  168.096 0 168.12 0.084 ;
    END
  END xs_q0[169]
  PIN xs_q0[16]
    DIRECTION INPUT ;
    USE SIGNAL ;
    PORT
      LAYER M5 ;
        RECT  153.408 0 153.432 0.084 ;
    END
  END xs_q0[16]
  PIN xs_q0[170]
    DIRECTION INPUT ;
    USE SIGNAL ;
    PORT
      LAYER M5 ;
        RECT  168.192 0 168.216 0.084 ;
    END
  END xs_q0[170]
  PIN xs_q0[171]
    DIRECTION INPUT ;
    USE SIGNAL ;
    PORT
      LAYER M5 ;
        RECT  168.288 0 168.312 0.084 ;
    END
  END xs_q0[171]
  PIN xs_q0[172]
    DIRECTION INPUT ;
    USE SIGNAL ;
    PORT
      LAYER M5 ;
        RECT  168.384 0 168.408 0.084 ;
    END
  END xs_q0[172]
  PIN xs_q0[173]
    DIRECTION INPUT ;
    USE SIGNAL ;
    PORT
      LAYER M5 ;
        RECT  168.48 0 168.504 0.084 ;
    END
  END xs_q0[173]
  PIN xs_q0[174]
    DIRECTION INPUT ;
    USE SIGNAL ;
    PORT
      LAYER M5 ;
        RECT  168.576 0 168.6 0.084 ;
    END
  END xs_q0[174]
  PIN xs_q0[175]
    DIRECTION INPUT ;
    USE SIGNAL ;
    PORT
      LAYER M5 ;
        RECT  168.672 0 168.696 0.084 ;
    END
  END xs_q0[175]
  PIN xs_q0[176]
    DIRECTION INPUT ;
    USE SIGNAL ;
    PORT
      LAYER M5 ;
        RECT  168.768 0 168.792 0.084 ;
    END
  END xs_q0[176]
  PIN xs_q0[177]
    DIRECTION INPUT ;
    USE SIGNAL ;
    PORT
      LAYER M5 ;
        RECT  168.864 0 168.888 0.084 ;
    END
  END xs_q0[177]
  PIN xs_q0[178]
    DIRECTION INPUT ;
    USE SIGNAL ;
    PORT
      LAYER M5 ;
        RECT  168.96 0 168.984 0.084 ;
    END
  END xs_q0[178]
  PIN xs_q0[179]
    DIRECTION INPUT ;
    USE SIGNAL ;
    PORT
      LAYER M5 ;
        RECT  169.056 0 169.08 0.084 ;
    END
  END xs_q0[179]
  PIN xs_q0[17]
    DIRECTION INPUT ;
    USE SIGNAL ;
    PORT
      LAYER M5 ;
        RECT  153.504 0 153.528 0.084 ;
    END
  END xs_q0[17]
  PIN xs_q0[180]
    DIRECTION INPUT ;
    USE SIGNAL ;
    PORT
      LAYER M5 ;
        RECT  169.152 0 169.176 0.084 ;
    END
  END xs_q0[180]
  PIN xs_q0[181]
    DIRECTION INPUT ;
    USE SIGNAL ;
    PORT
      LAYER M5 ;
        RECT  169.248 0 169.272 0.084 ;
    END
  END xs_q0[181]
  PIN xs_q0[182]
    DIRECTION INPUT ;
    USE SIGNAL ;
    PORT
      LAYER M5 ;
        RECT  169.344 0 169.368 0.084 ;
    END
  END xs_q0[182]
  PIN xs_q0[183]
    DIRECTION INPUT ;
    USE SIGNAL ;
    PORT
      LAYER M5 ;
        RECT  169.44 0 169.464 0.084 ;
    END
  END xs_q0[183]
  PIN xs_q0[184]
    DIRECTION INPUT ;
    USE SIGNAL ;
    PORT
      LAYER M5 ;
        RECT  169.536 0 169.56 0.084 ;
    END
  END xs_q0[184]
  PIN xs_q0[185]
    DIRECTION INPUT ;
    USE SIGNAL ;
    PORT
      LAYER M5 ;
        RECT  169.632 0 169.656 0.084 ;
    END
  END xs_q0[185]
  PIN xs_q0[186]
    DIRECTION INPUT ;
    USE SIGNAL ;
    PORT
      LAYER M5 ;
        RECT  169.728 0 169.752 0.084 ;
    END
  END xs_q0[186]
  PIN xs_q0[187]
    DIRECTION INPUT ;
    USE SIGNAL ;
    PORT
      LAYER M5 ;
        RECT  169.824 0 169.848 0.084 ;
    END
  END xs_q0[187]
  PIN xs_q0[188]
    DIRECTION INPUT ;
    USE SIGNAL ;
    PORT
      LAYER M5 ;
        RECT  169.92 0 169.944 0.084 ;
    END
  END xs_q0[188]
  PIN xs_q0[189]
    DIRECTION INPUT ;
    USE SIGNAL ;
    PORT
      LAYER M5 ;
        RECT  170.016 0 170.04 0.084 ;
    END
  END xs_q0[189]
  PIN xs_q0[18]
    DIRECTION INPUT ;
    USE SIGNAL ;
    PORT
      LAYER M5 ;
        RECT  153.6 0 153.624 0.084 ;
    END
  END xs_q0[18]
  PIN xs_q0[190]
    DIRECTION INPUT ;
    USE SIGNAL ;
    PORT
      LAYER M5 ;
        RECT  170.112 0 170.136 0.084 ;
    END
  END xs_q0[190]
  PIN xs_q0[191]
    DIRECTION INPUT ;
    USE SIGNAL ;
    PORT
      LAYER M5 ;
        RECT  170.208 0 170.232 0.084 ;
    END
  END xs_q0[191]
  PIN xs_q0[192]
    DIRECTION INPUT ;
    USE SIGNAL ;
    PORT
      LAYER M5 ;
        RECT  170.304 0 170.328 0.084 ;
    END
  END xs_q0[192]
  PIN xs_q0[193]
    DIRECTION INPUT ;
    USE SIGNAL ;
    PORT
      LAYER M5 ;
        RECT  170.4 0 170.424 0.084 ;
    END
  END xs_q0[193]
  PIN xs_q0[194]
    DIRECTION INPUT ;
    USE SIGNAL ;
    PORT
      LAYER M5 ;
        RECT  170.496 0 170.52 0.084 ;
    END
  END xs_q0[194]
  PIN xs_q0[195]
    DIRECTION INPUT ;
    USE SIGNAL ;
    PORT
      LAYER M5 ;
        RECT  170.592 0 170.616 0.084 ;
    END
  END xs_q0[195]
  PIN xs_q0[196]
    DIRECTION INPUT ;
    USE SIGNAL ;
    PORT
      LAYER M5 ;
        RECT  170.688 0 170.712 0.084 ;
    END
  END xs_q0[196]
  PIN xs_q0[197]
    DIRECTION INPUT ;
    USE SIGNAL ;
    PORT
      LAYER M5 ;
        RECT  170.784 0 170.808 0.084 ;
    END
  END xs_q0[197]
  PIN xs_q0[198]
    DIRECTION INPUT ;
    USE SIGNAL ;
    PORT
      LAYER M5 ;
        RECT  170.88 0 170.904 0.084 ;
    END
  END xs_q0[198]
  PIN xs_q0[199]
    DIRECTION INPUT ;
    USE SIGNAL ;
    PORT
      LAYER M5 ;
        RECT  170.976 0 171 0.084 ;
    END
  END xs_q0[199]
  PIN xs_q0[19]
    DIRECTION INPUT ;
    USE SIGNAL ;
    PORT
      LAYER M5 ;
        RECT  153.696 0 153.72 0.084 ;
    END
  END xs_q0[19]
  PIN xs_q0[1]
    DIRECTION INPUT ;
    USE SIGNAL ;
    PORT
      LAYER M5 ;
        RECT  151.968 0 151.992 0.084 ;
    END
  END xs_q0[1]
  PIN xs_q0[200]
    DIRECTION INPUT ;
    USE SIGNAL ;
    PORT
      LAYER M5 ;
        RECT  171.072 0 171.096 0.084 ;
    END
  END xs_q0[200]
  PIN xs_q0[201]
    DIRECTION INPUT ;
    USE SIGNAL ;
    PORT
      LAYER M5 ;
        RECT  171.168 0 171.192 0.084 ;
    END
  END xs_q0[201]
  PIN xs_q0[202]
    DIRECTION INPUT ;
    USE SIGNAL ;
    PORT
      LAYER M5 ;
        RECT  171.264 0 171.288 0.084 ;
    END
  END xs_q0[202]
  PIN xs_q0[203]
    DIRECTION INPUT ;
    USE SIGNAL ;
    PORT
      LAYER M5 ;
        RECT  171.36 0 171.384 0.084 ;
    END
  END xs_q0[203]
  PIN xs_q0[204]
    DIRECTION INPUT ;
    USE SIGNAL ;
    PORT
      LAYER M5 ;
        RECT  171.456 0 171.48 0.084 ;
    END
  END xs_q0[204]
  PIN xs_q0[205]
    DIRECTION INPUT ;
    USE SIGNAL ;
    PORT
      LAYER M5 ;
        RECT  171.552 0 171.576 0.084 ;
    END
  END xs_q0[205]
  PIN xs_q0[206]
    DIRECTION INPUT ;
    USE SIGNAL ;
    PORT
      LAYER M5 ;
        RECT  171.648 0 171.672 0.084 ;
    END
  END xs_q0[206]
  PIN xs_q0[207]
    DIRECTION INPUT ;
    USE SIGNAL ;
    PORT
      LAYER M5 ;
        RECT  171.744 0 171.768 0.084 ;
    END
  END xs_q0[207]
  PIN xs_q0[208]
    DIRECTION INPUT ;
    USE SIGNAL ;
    PORT
      LAYER M5 ;
        RECT  171.84 0 171.864 0.084 ;
    END
  END xs_q0[208]
  PIN xs_q0[209]
    DIRECTION INPUT ;
    USE SIGNAL ;
    PORT
      LAYER M5 ;
        RECT  171.936 0 171.96 0.084 ;
    END
  END xs_q0[209]
  PIN xs_q0[20]
    DIRECTION INPUT ;
    USE SIGNAL ;
    PORT
      LAYER M5 ;
        RECT  153.792 0 153.816 0.084 ;
    END
  END xs_q0[20]
  PIN xs_q0[210]
    DIRECTION INPUT ;
    USE SIGNAL ;
    PORT
      LAYER M5 ;
        RECT  172.032 0 172.056 0.084 ;
    END
  END xs_q0[210]
  PIN xs_q0[211]
    DIRECTION INPUT ;
    USE SIGNAL ;
    PORT
      LAYER M5 ;
        RECT  172.128 0 172.152 0.084 ;
    END
  END xs_q0[211]
  PIN xs_q0[212]
    DIRECTION INPUT ;
    USE SIGNAL ;
    PORT
      LAYER M5 ;
        RECT  172.224 0 172.248 0.084 ;
    END
  END xs_q0[212]
  PIN xs_q0[213]
    DIRECTION INPUT ;
    USE SIGNAL ;
    PORT
      LAYER M5 ;
        RECT  172.32 0 172.344 0.084 ;
    END
  END xs_q0[213]
  PIN xs_q0[214]
    DIRECTION INPUT ;
    USE SIGNAL ;
    PORT
      LAYER M5 ;
        RECT  172.416 0 172.44 0.084 ;
    END
  END xs_q0[214]
  PIN xs_q0[215]
    DIRECTION INPUT ;
    USE SIGNAL ;
    PORT
      LAYER M5 ;
        RECT  172.512 0 172.536 0.084 ;
    END
  END xs_q0[215]
  PIN xs_q0[216]
    DIRECTION INPUT ;
    USE SIGNAL ;
    PORT
      LAYER M5 ;
        RECT  172.608 0 172.632 0.084 ;
    END
  END xs_q0[216]
  PIN xs_q0[217]
    DIRECTION INPUT ;
    USE SIGNAL ;
    PORT
      LAYER M5 ;
        RECT  172.704 0 172.728 0.084 ;
    END
  END xs_q0[217]
  PIN xs_q0[218]
    DIRECTION INPUT ;
    USE SIGNAL ;
    PORT
      LAYER M5 ;
        RECT  172.8 0 172.824 0.084 ;
    END
  END xs_q0[218]
  PIN xs_q0[219]
    DIRECTION INPUT ;
    USE SIGNAL ;
    PORT
      LAYER M5 ;
        RECT  172.896 0 172.92 0.084 ;
    END
  END xs_q0[219]
  PIN xs_q0[21]
    DIRECTION INPUT ;
    USE SIGNAL ;
    PORT
      LAYER M5 ;
        RECT  153.888 0 153.912 0.084 ;
    END
  END xs_q0[21]
  PIN xs_q0[220]
    DIRECTION INPUT ;
    USE SIGNAL ;
    PORT
      LAYER M5 ;
        RECT  172.992 0 173.016 0.084 ;
    END
  END xs_q0[220]
  PIN xs_q0[221]
    DIRECTION INPUT ;
    USE SIGNAL ;
    PORT
      LAYER M5 ;
        RECT  173.088 0 173.112 0.084 ;
    END
  END xs_q0[221]
  PIN xs_q0[222]
    DIRECTION INPUT ;
    USE SIGNAL ;
    PORT
      LAYER M5 ;
        RECT  173.184 0 173.208 0.084 ;
    END
  END xs_q0[222]
  PIN xs_q0[223]
    DIRECTION INPUT ;
    USE SIGNAL ;
    PORT
      LAYER M5 ;
        RECT  173.28 0 173.304 0.084 ;
    END
  END xs_q0[223]
  PIN xs_q0[224]
    DIRECTION INPUT ;
    USE SIGNAL ;
    PORT
      LAYER M5 ;
        RECT  173.376 0 173.4 0.084 ;
    END
  END xs_q0[224]
  PIN xs_q0[225]
    DIRECTION INPUT ;
    USE SIGNAL ;
    PORT
      LAYER M5 ;
        RECT  173.472 0 173.496 0.084 ;
    END
  END xs_q0[225]
  PIN xs_q0[226]
    DIRECTION INPUT ;
    USE SIGNAL ;
    PORT
      LAYER M5 ;
        RECT  173.568 0 173.592 0.084 ;
    END
  END xs_q0[226]
  PIN xs_q0[227]
    DIRECTION INPUT ;
    USE SIGNAL ;
    PORT
      LAYER M5 ;
        RECT  173.664 0 173.688 0.084 ;
    END
  END xs_q0[227]
  PIN xs_q0[228]
    DIRECTION INPUT ;
    USE SIGNAL ;
    PORT
      LAYER M5 ;
        RECT  173.76 0 173.784 0.084 ;
    END
  END xs_q0[228]
  PIN xs_q0[229]
    DIRECTION INPUT ;
    USE SIGNAL ;
    PORT
      LAYER M5 ;
        RECT  173.856 0 173.88 0.084 ;
    END
  END xs_q0[229]
  PIN xs_q0[22]
    DIRECTION INPUT ;
    USE SIGNAL ;
    PORT
      LAYER M5 ;
        RECT  153.984 0 154.008 0.084 ;
    END
  END xs_q0[22]
  PIN xs_q0[230]
    DIRECTION INPUT ;
    USE SIGNAL ;
    PORT
      LAYER M5 ;
        RECT  173.952 0 173.976 0.084 ;
    END
  END xs_q0[230]
  PIN xs_q0[231]
    DIRECTION INPUT ;
    USE SIGNAL ;
    PORT
      LAYER M5 ;
        RECT  174.048 0 174.072 0.084 ;
    END
  END xs_q0[231]
  PIN xs_q0[232]
    DIRECTION INPUT ;
    USE SIGNAL ;
    PORT
      LAYER M5 ;
        RECT  174.144 0 174.168 0.084 ;
    END
  END xs_q0[232]
  PIN xs_q0[233]
    DIRECTION INPUT ;
    USE SIGNAL ;
    PORT
      LAYER M5 ;
        RECT  174.24 0 174.264 0.084 ;
    END
  END xs_q0[233]
  PIN xs_q0[234]
    DIRECTION INPUT ;
    USE SIGNAL ;
    PORT
      LAYER M5 ;
        RECT  174.336 0 174.36 0.084 ;
    END
  END xs_q0[234]
  PIN xs_q0[235]
    DIRECTION INPUT ;
    USE SIGNAL ;
    PORT
      LAYER M5 ;
        RECT  174.432 0 174.456 0.084 ;
    END
  END xs_q0[235]
  PIN xs_q0[236]
    DIRECTION INPUT ;
    USE SIGNAL ;
    PORT
      LAYER M5 ;
        RECT  174.528 0 174.552 0.084 ;
    END
  END xs_q0[236]
  PIN xs_q0[237]
    DIRECTION INPUT ;
    USE SIGNAL ;
    PORT
      LAYER M5 ;
        RECT  174.624 0 174.648 0.084 ;
    END
  END xs_q0[237]
  PIN xs_q0[238]
    DIRECTION INPUT ;
    USE SIGNAL ;
    PORT
      LAYER M5 ;
        RECT  174.72 0 174.744 0.084 ;
    END
  END xs_q0[238]
  PIN xs_q0[239]
    DIRECTION INPUT ;
    USE SIGNAL ;
    PORT
      LAYER M5 ;
        RECT  174.816 0 174.84 0.084 ;
    END
  END xs_q0[239]
  PIN xs_q0[23]
    DIRECTION INPUT ;
    USE SIGNAL ;
    PORT
      LAYER M5 ;
        RECT  154.08 0 154.104 0.084 ;
    END
  END xs_q0[23]
  PIN xs_q0[240]
    DIRECTION INPUT ;
    USE SIGNAL ;
    PORT
      LAYER M5 ;
        RECT  174.912 0 174.936 0.084 ;
    END
  END xs_q0[240]
  PIN xs_q0[241]
    DIRECTION INPUT ;
    USE SIGNAL ;
    PORT
      LAYER M5 ;
        RECT  175.008 0 175.032 0.084 ;
    END
  END xs_q0[241]
  PIN xs_q0[242]
    DIRECTION INPUT ;
    USE SIGNAL ;
    PORT
      LAYER M5 ;
        RECT  175.104 0 175.128 0.084 ;
    END
  END xs_q0[242]
  PIN xs_q0[243]
    DIRECTION INPUT ;
    USE SIGNAL ;
    PORT
      LAYER M5 ;
        RECT  175.2 0 175.224 0.084 ;
    END
  END xs_q0[243]
  PIN xs_q0[244]
    DIRECTION INPUT ;
    USE SIGNAL ;
    PORT
      LAYER M5 ;
        RECT  175.296 0 175.32 0.084 ;
    END
  END xs_q0[244]
  PIN xs_q0[245]
    DIRECTION INPUT ;
    USE SIGNAL ;
    PORT
      LAYER M5 ;
        RECT  175.392 0 175.416 0.084 ;
    END
  END xs_q0[245]
  PIN xs_q0[246]
    DIRECTION INPUT ;
    USE SIGNAL ;
    PORT
      LAYER M5 ;
        RECT  175.488 0 175.512 0.084 ;
    END
  END xs_q0[246]
  PIN xs_q0[247]
    DIRECTION INPUT ;
    USE SIGNAL ;
    PORT
      LAYER M5 ;
        RECT  175.584 0 175.608 0.084 ;
    END
  END xs_q0[247]
  PIN xs_q0[248]
    DIRECTION INPUT ;
    USE SIGNAL ;
    PORT
      LAYER M5 ;
        RECT  175.68 0 175.704 0.084 ;
    END
  END xs_q0[248]
  PIN xs_q0[249]
    DIRECTION INPUT ;
    USE SIGNAL ;
    PORT
      LAYER M5 ;
        RECT  175.776 0 175.8 0.084 ;
    END
  END xs_q0[249]
  PIN xs_q0[24]
    DIRECTION INPUT ;
    USE SIGNAL ;
    PORT
      LAYER M5 ;
        RECT  154.176 0 154.2 0.084 ;
    END
  END xs_q0[24]
  PIN xs_q0[250]
    DIRECTION INPUT ;
    USE SIGNAL ;
    PORT
      LAYER M5 ;
        RECT  175.872 0 175.896 0.084 ;
    END
  END xs_q0[250]
  PIN xs_q0[251]
    DIRECTION INPUT ;
    USE SIGNAL ;
    PORT
      LAYER M5 ;
        RECT  175.968 0 175.992 0.084 ;
    END
  END xs_q0[251]
  PIN xs_q0[252]
    DIRECTION INPUT ;
    USE SIGNAL ;
    PORT
      LAYER M5 ;
        RECT  176.064 0 176.088 0.084 ;
    END
  END xs_q0[252]
  PIN xs_q0[253]
    DIRECTION INPUT ;
    USE SIGNAL ;
    PORT
      LAYER M5 ;
        RECT  176.16 0 176.184 0.084 ;
    END
  END xs_q0[253]
  PIN xs_q0[254]
    DIRECTION INPUT ;
    USE SIGNAL ;
    PORT
      LAYER M5 ;
        RECT  176.256 0 176.28 0.084 ;
    END
  END xs_q0[254]
  PIN xs_q0[255]
    DIRECTION INPUT ;
    USE SIGNAL ;
    PORT
      LAYER M5 ;
        RECT  176.352 0 176.376 0.084 ;
    END
  END xs_q0[255]
  PIN xs_q0[25]
    DIRECTION INPUT ;
    USE SIGNAL ;
    PORT
      LAYER M5 ;
        RECT  154.272 0 154.296 0.084 ;
    END
  END xs_q0[25]
  PIN xs_q0[26]
    DIRECTION INPUT ;
    USE SIGNAL ;
    PORT
      LAYER M5 ;
        RECT  154.368 0 154.392 0.084 ;
    END
  END xs_q0[26]
  PIN xs_q0[27]
    DIRECTION INPUT ;
    USE SIGNAL ;
    PORT
      LAYER M5 ;
        RECT  154.464 0 154.488 0.084 ;
    END
  END xs_q0[27]
  PIN xs_q0[28]
    DIRECTION INPUT ;
    USE SIGNAL ;
    PORT
      LAYER M5 ;
        RECT  154.56 0 154.584 0.084 ;
    END
  END xs_q0[28]
  PIN xs_q0[29]
    DIRECTION INPUT ;
    USE SIGNAL ;
    PORT
      LAYER M5 ;
        RECT  154.656 0 154.68 0.084 ;
    END
  END xs_q0[29]
  PIN xs_q0[2]
    DIRECTION INPUT ;
    USE SIGNAL ;
    PORT
      LAYER M5 ;
        RECT  152.064 0 152.088 0.084 ;
    END
  END xs_q0[2]
  PIN xs_q0[30]
    DIRECTION INPUT ;
    USE SIGNAL ;
    PORT
      LAYER M5 ;
        RECT  154.752 0 154.776 0.084 ;
    END
  END xs_q0[30]
  PIN xs_q0[31]
    DIRECTION INPUT ;
    USE SIGNAL ;
    PORT
      LAYER M5 ;
        RECT  154.848 0 154.872 0.084 ;
    END
  END xs_q0[31]
  PIN xs_q0[32]
    DIRECTION INPUT ;
    USE SIGNAL ;
    PORT
      LAYER M5 ;
        RECT  154.944 0 154.968 0.084 ;
    END
  END xs_q0[32]
  PIN xs_q0[33]
    DIRECTION INPUT ;
    USE SIGNAL ;
    PORT
      LAYER M5 ;
        RECT  155.04 0 155.064 0.084 ;
    END
  END xs_q0[33]
  PIN xs_q0[34]
    DIRECTION INPUT ;
    USE SIGNAL ;
    PORT
      LAYER M5 ;
        RECT  155.136 0 155.16 0.084 ;
    END
  END xs_q0[34]
  PIN xs_q0[35]
    DIRECTION INPUT ;
    USE SIGNAL ;
    PORT
      LAYER M5 ;
        RECT  155.232 0 155.256 0.084 ;
    END
  END xs_q0[35]
  PIN xs_q0[36]
    DIRECTION INPUT ;
    USE SIGNAL ;
    PORT
      LAYER M5 ;
        RECT  155.328 0 155.352 0.084 ;
    END
  END xs_q0[36]
  PIN xs_q0[37]
    DIRECTION INPUT ;
    USE SIGNAL ;
    PORT
      LAYER M5 ;
        RECT  155.424 0 155.448 0.084 ;
    END
  END xs_q0[37]
  PIN xs_q0[38]
    DIRECTION INPUT ;
    USE SIGNAL ;
    PORT
      LAYER M5 ;
        RECT  155.52 0 155.544 0.084 ;
    END
  END xs_q0[38]
  PIN xs_q0[39]
    DIRECTION INPUT ;
    USE SIGNAL ;
    PORT
      LAYER M5 ;
        RECT  155.616 0 155.64 0.084 ;
    END
  END xs_q0[39]
  PIN xs_q0[3]
    DIRECTION INPUT ;
    USE SIGNAL ;
    PORT
      LAYER M5 ;
        RECT  152.16 0 152.184 0.084 ;
    END
  END xs_q0[3]
  PIN xs_q0[40]
    DIRECTION INPUT ;
    USE SIGNAL ;
    PORT
      LAYER M5 ;
        RECT  155.712 0 155.736 0.084 ;
    END
  END xs_q0[40]
  PIN xs_q0[41]
    DIRECTION INPUT ;
    USE SIGNAL ;
    PORT
      LAYER M5 ;
        RECT  155.808 0 155.832 0.084 ;
    END
  END xs_q0[41]
  PIN xs_q0[42]
    DIRECTION INPUT ;
    USE SIGNAL ;
    PORT
      LAYER M5 ;
        RECT  155.904 0 155.928 0.084 ;
    END
  END xs_q0[42]
  PIN xs_q0[43]
    DIRECTION INPUT ;
    USE SIGNAL ;
    PORT
      LAYER M5 ;
        RECT  156 0 156.024 0.084 ;
    END
  END xs_q0[43]
  PIN xs_q0[44]
    DIRECTION INPUT ;
    USE SIGNAL ;
    PORT
      LAYER M5 ;
        RECT  156.096 0 156.12 0.084 ;
    END
  END xs_q0[44]
  PIN xs_q0[45]
    DIRECTION INPUT ;
    USE SIGNAL ;
    PORT
      LAYER M5 ;
        RECT  156.192 0 156.216 0.084 ;
    END
  END xs_q0[45]
  PIN xs_q0[46]
    DIRECTION INPUT ;
    USE SIGNAL ;
    PORT
      LAYER M5 ;
        RECT  156.288 0 156.312 0.084 ;
    END
  END xs_q0[46]
  PIN xs_q0[47]
    DIRECTION INPUT ;
    USE SIGNAL ;
    PORT
      LAYER M5 ;
        RECT  156.384 0 156.408 0.084 ;
    END
  END xs_q0[47]
  PIN xs_q0[48]
    DIRECTION INPUT ;
    USE SIGNAL ;
    PORT
      LAYER M5 ;
        RECT  156.48 0 156.504 0.084 ;
    END
  END xs_q0[48]
  PIN xs_q0[49]
    DIRECTION INPUT ;
    USE SIGNAL ;
    PORT
      LAYER M5 ;
        RECT  156.576 0 156.6 0.084 ;
    END
  END xs_q0[49]
  PIN xs_q0[4]
    DIRECTION INPUT ;
    USE SIGNAL ;
    PORT
      LAYER M5 ;
        RECT  152.256 0 152.28 0.084 ;
    END
  END xs_q0[4]
  PIN xs_q0[50]
    DIRECTION INPUT ;
    USE SIGNAL ;
    PORT
      LAYER M5 ;
        RECT  156.672 0 156.696 0.084 ;
    END
  END xs_q0[50]
  PIN xs_q0[51]
    DIRECTION INPUT ;
    USE SIGNAL ;
    PORT
      LAYER M5 ;
        RECT  156.768 0 156.792 0.084 ;
    END
  END xs_q0[51]
  PIN xs_q0[52]
    DIRECTION INPUT ;
    USE SIGNAL ;
    PORT
      LAYER M5 ;
        RECT  156.864 0 156.888 0.084 ;
    END
  END xs_q0[52]
  PIN xs_q0[53]
    DIRECTION INPUT ;
    USE SIGNAL ;
    PORT
      LAYER M5 ;
        RECT  156.96 0 156.984 0.084 ;
    END
  END xs_q0[53]
  PIN xs_q0[54]
    DIRECTION INPUT ;
    USE SIGNAL ;
    PORT
      LAYER M5 ;
        RECT  157.056 0 157.08 0.084 ;
    END
  END xs_q0[54]
  PIN xs_q0[55]
    DIRECTION INPUT ;
    USE SIGNAL ;
    PORT
      LAYER M5 ;
        RECT  157.152 0 157.176 0.084 ;
    END
  END xs_q0[55]
  PIN xs_q0[56]
    DIRECTION INPUT ;
    USE SIGNAL ;
    PORT
      LAYER M5 ;
        RECT  157.248 0 157.272 0.084 ;
    END
  END xs_q0[56]
  PIN xs_q0[57]
    DIRECTION INPUT ;
    USE SIGNAL ;
    PORT
      LAYER M5 ;
        RECT  157.344 0 157.368 0.084 ;
    END
  END xs_q0[57]
  PIN xs_q0[58]
    DIRECTION INPUT ;
    USE SIGNAL ;
    PORT
      LAYER M5 ;
        RECT  157.44 0 157.464 0.084 ;
    END
  END xs_q0[58]
  PIN xs_q0[59]
    DIRECTION INPUT ;
    USE SIGNAL ;
    PORT
      LAYER M5 ;
        RECT  157.536 0 157.56 0.084 ;
    END
  END xs_q0[59]
  PIN xs_q0[5]
    DIRECTION INPUT ;
    USE SIGNAL ;
    PORT
      LAYER M5 ;
        RECT  152.352 0 152.376 0.084 ;
    END
  END xs_q0[5]
  PIN xs_q0[60]
    DIRECTION INPUT ;
    USE SIGNAL ;
    PORT
      LAYER M5 ;
        RECT  157.632 0 157.656 0.084 ;
    END
  END xs_q0[60]
  PIN xs_q0[61]
    DIRECTION INPUT ;
    USE SIGNAL ;
    PORT
      LAYER M5 ;
        RECT  157.728 0 157.752 0.084 ;
    END
  END xs_q0[61]
  PIN xs_q0[62]
    DIRECTION INPUT ;
    USE SIGNAL ;
    PORT
      LAYER M5 ;
        RECT  157.824 0 157.848 0.084 ;
    END
  END xs_q0[62]
  PIN xs_q0[63]
    DIRECTION INPUT ;
    USE SIGNAL ;
    PORT
      LAYER M5 ;
        RECT  157.92 0 157.944 0.084 ;
    END
  END xs_q0[63]
  PIN xs_q0[64]
    DIRECTION INPUT ;
    USE SIGNAL ;
    PORT
      LAYER M5 ;
        RECT  158.016 0 158.04 0.084 ;
    END
  END xs_q0[64]
  PIN xs_q0[65]
    DIRECTION INPUT ;
    USE SIGNAL ;
    PORT
      LAYER M5 ;
        RECT  158.112 0 158.136 0.084 ;
    END
  END xs_q0[65]
  PIN xs_q0[66]
    DIRECTION INPUT ;
    USE SIGNAL ;
    PORT
      LAYER M5 ;
        RECT  158.208 0 158.232 0.084 ;
    END
  END xs_q0[66]
  PIN xs_q0[67]
    DIRECTION INPUT ;
    USE SIGNAL ;
    PORT
      LAYER M5 ;
        RECT  158.304 0 158.328 0.084 ;
    END
  END xs_q0[67]
  PIN xs_q0[68]
    DIRECTION INPUT ;
    USE SIGNAL ;
    PORT
      LAYER M5 ;
        RECT  158.4 0 158.424 0.084 ;
    END
  END xs_q0[68]
  PIN xs_q0[69]
    DIRECTION INPUT ;
    USE SIGNAL ;
    PORT
      LAYER M5 ;
        RECT  158.496 0 158.52 0.084 ;
    END
  END xs_q0[69]
  PIN xs_q0[6]
    DIRECTION INPUT ;
    USE SIGNAL ;
    PORT
      LAYER M5 ;
        RECT  152.448 0 152.472 0.084 ;
    END
  END xs_q0[6]
  PIN xs_q0[70]
    DIRECTION INPUT ;
    USE SIGNAL ;
    PORT
      LAYER M5 ;
        RECT  158.592 0 158.616 0.084 ;
    END
  END xs_q0[70]
  PIN xs_q0[71]
    DIRECTION INPUT ;
    USE SIGNAL ;
    PORT
      LAYER M5 ;
        RECT  158.688 0 158.712 0.084 ;
    END
  END xs_q0[71]
  PIN xs_q0[72]
    DIRECTION INPUT ;
    USE SIGNAL ;
    PORT
      LAYER M5 ;
        RECT  158.784 0 158.808 0.084 ;
    END
  END xs_q0[72]
  PIN xs_q0[73]
    DIRECTION INPUT ;
    USE SIGNAL ;
    PORT
      LAYER M5 ;
        RECT  158.88 0 158.904 0.084 ;
    END
  END xs_q0[73]
  PIN xs_q0[74]
    DIRECTION INPUT ;
    USE SIGNAL ;
    PORT
      LAYER M5 ;
        RECT  158.976 0 159 0.084 ;
    END
  END xs_q0[74]
  PIN xs_q0[75]
    DIRECTION INPUT ;
    USE SIGNAL ;
    PORT
      LAYER M5 ;
        RECT  159.072 0 159.096 0.084 ;
    END
  END xs_q0[75]
  PIN xs_q0[76]
    DIRECTION INPUT ;
    USE SIGNAL ;
    PORT
      LAYER M5 ;
        RECT  159.168 0 159.192 0.084 ;
    END
  END xs_q0[76]
  PIN xs_q0[77]
    DIRECTION INPUT ;
    USE SIGNAL ;
    PORT
      LAYER M5 ;
        RECT  159.264 0 159.288 0.084 ;
    END
  END xs_q0[77]
  PIN xs_q0[78]
    DIRECTION INPUT ;
    USE SIGNAL ;
    PORT
      LAYER M5 ;
        RECT  159.36 0 159.384 0.084 ;
    END
  END xs_q0[78]
  PIN xs_q0[79]
    DIRECTION INPUT ;
    USE SIGNAL ;
    PORT
      LAYER M5 ;
        RECT  159.456 0 159.48 0.084 ;
    END
  END xs_q0[79]
  PIN xs_q0[7]
    DIRECTION INPUT ;
    USE SIGNAL ;
    PORT
      LAYER M5 ;
        RECT  152.544 0 152.568 0.084 ;
    END
  END xs_q0[7]
  PIN xs_q0[80]
    DIRECTION INPUT ;
    USE SIGNAL ;
    PORT
      LAYER M5 ;
        RECT  159.552 0 159.576 0.084 ;
    END
  END xs_q0[80]
  PIN xs_q0[81]
    DIRECTION INPUT ;
    USE SIGNAL ;
    PORT
      LAYER M5 ;
        RECT  159.648 0 159.672 0.084 ;
    END
  END xs_q0[81]
  PIN xs_q0[82]
    DIRECTION INPUT ;
    USE SIGNAL ;
    PORT
      LAYER M5 ;
        RECT  159.744 0 159.768 0.084 ;
    END
  END xs_q0[82]
  PIN xs_q0[83]
    DIRECTION INPUT ;
    USE SIGNAL ;
    PORT
      LAYER M5 ;
        RECT  159.84 0 159.864 0.084 ;
    END
  END xs_q0[83]
  PIN xs_q0[84]
    DIRECTION INPUT ;
    USE SIGNAL ;
    PORT
      LAYER M5 ;
        RECT  159.936 0 159.96 0.084 ;
    END
  END xs_q0[84]
  PIN xs_q0[85]
    DIRECTION INPUT ;
    USE SIGNAL ;
    PORT
      LAYER M5 ;
        RECT  160.032 0 160.056 0.084 ;
    END
  END xs_q0[85]
  PIN xs_q0[86]
    DIRECTION INPUT ;
    USE SIGNAL ;
    PORT
      LAYER M5 ;
        RECT  160.128 0 160.152 0.084 ;
    END
  END xs_q0[86]
  PIN xs_q0[87]
    DIRECTION INPUT ;
    USE SIGNAL ;
    PORT
      LAYER M5 ;
        RECT  160.224 0 160.248 0.084 ;
    END
  END xs_q0[87]
  PIN xs_q0[88]
    DIRECTION INPUT ;
    USE SIGNAL ;
    PORT
      LAYER M5 ;
        RECT  160.32 0 160.344 0.084 ;
    END
  END xs_q0[88]
  PIN xs_q0[89]
    DIRECTION INPUT ;
    USE SIGNAL ;
    PORT
      LAYER M5 ;
        RECT  160.416 0 160.44 0.084 ;
    END
  END xs_q0[89]
  PIN xs_q0[8]
    DIRECTION INPUT ;
    USE SIGNAL ;
    PORT
      LAYER M5 ;
        RECT  152.64 0 152.664 0.084 ;
    END
  END xs_q0[8]
  PIN xs_q0[90]
    DIRECTION INPUT ;
    USE SIGNAL ;
    PORT
      LAYER M5 ;
        RECT  160.512 0 160.536 0.084 ;
    END
  END xs_q0[90]
  PIN xs_q0[91]
    DIRECTION INPUT ;
    USE SIGNAL ;
    PORT
      LAYER M5 ;
        RECT  160.608 0 160.632 0.084 ;
    END
  END xs_q0[91]
  PIN xs_q0[92]
    DIRECTION INPUT ;
    USE SIGNAL ;
    PORT
      LAYER M5 ;
        RECT  160.704 0 160.728 0.084 ;
    END
  END xs_q0[92]
  PIN xs_q0[93]
    DIRECTION INPUT ;
    USE SIGNAL ;
    PORT
      LAYER M5 ;
        RECT  160.8 0 160.824 0.084 ;
    END
  END xs_q0[93]
  PIN xs_q0[94]
    DIRECTION INPUT ;
    USE SIGNAL ;
    PORT
      LAYER M5 ;
        RECT  160.896 0 160.92 0.084 ;
    END
  END xs_q0[94]
  PIN xs_q0[95]
    DIRECTION INPUT ;
    USE SIGNAL ;
    PORT
      LAYER M5 ;
        RECT  160.992 0 161.016 0.084 ;
    END
  END xs_q0[95]
  PIN xs_q0[96]
    DIRECTION INPUT ;
    USE SIGNAL ;
    PORT
      LAYER M5 ;
        RECT  161.088 0 161.112 0.084 ;
    END
  END xs_q0[96]
  PIN xs_q0[97]
    DIRECTION INPUT ;
    USE SIGNAL ;
    PORT
      LAYER M5 ;
        RECT  161.184 0 161.208 0.084 ;
    END
  END xs_q0[97]
  PIN xs_q0[98]
    DIRECTION INPUT ;
    USE SIGNAL ;
    PORT
      LAYER M5 ;
        RECT  161.28 0 161.304 0.084 ;
    END
  END xs_q0[98]
  PIN xs_q0[99]
    DIRECTION INPUT ;
    USE SIGNAL ;
    PORT
      LAYER M5 ;
        RECT  161.376 0 161.4 0.084 ;
    END
  END xs_q0[99]
  PIN xs_q0[9]
    DIRECTION INPUT ;
    USE SIGNAL ;
    PORT
      LAYER M5 ;
        RECT  152.736 0 152.76 0.084 ;
    END
  END xs_q0[9]
  PIN xs_q1[0]
    DIRECTION INPUT ;
    USE SIGNAL ;
    PORT
      LAYER M5 ;
        RECT  176.448 0 176.472 0.084 ;
    END
  END xs_q1[0]
  PIN xs_q1[100]
    DIRECTION INPUT ;
    USE SIGNAL ;
    PORT
      LAYER M5 ;
        RECT  186.048 0 186.072 0.084 ;
    END
  END xs_q1[100]
  PIN xs_q1[101]
    DIRECTION INPUT ;
    USE SIGNAL ;
    PORT
      LAYER M5 ;
        RECT  186.144 0 186.168 0.084 ;
    END
  END xs_q1[101]
  PIN xs_q1[102]
    DIRECTION INPUT ;
    USE SIGNAL ;
    PORT
      LAYER M5 ;
        RECT  186.24 0 186.264 0.084 ;
    END
  END xs_q1[102]
  PIN xs_q1[103]
    DIRECTION INPUT ;
    USE SIGNAL ;
    PORT
      LAYER M5 ;
        RECT  186.336 0 186.36 0.084 ;
    END
  END xs_q1[103]
  PIN xs_q1[104]
    DIRECTION INPUT ;
    USE SIGNAL ;
    PORT
      LAYER M5 ;
        RECT  186.432 0 186.456 0.084 ;
    END
  END xs_q1[104]
  PIN xs_q1[105]
    DIRECTION INPUT ;
    USE SIGNAL ;
    PORT
      LAYER M5 ;
        RECT  186.528 0 186.552 0.084 ;
    END
  END xs_q1[105]
  PIN xs_q1[106]
    DIRECTION INPUT ;
    USE SIGNAL ;
    PORT
      LAYER M5 ;
        RECT  186.624 0 186.648 0.084 ;
    END
  END xs_q1[106]
  PIN xs_q1[107]
    DIRECTION INPUT ;
    USE SIGNAL ;
    PORT
      LAYER M5 ;
        RECT  186.72 0 186.744 0.084 ;
    END
  END xs_q1[107]
  PIN xs_q1[108]
    DIRECTION INPUT ;
    USE SIGNAL ;
    PORT
      LAYER M5 ;
        RECT  186.816 0 186.84 0.084 ;
    END
  END xs_q1[108]
  PIN xs_q1[109]
    DIRECTION INPUT ;
    USE SIGNAL ;
    PORT
      LAYER M5 ;
        RECT  186.912 0 186.936 0.084 ;
    END
  END xs_q1[109]
  PIN xs_q1[10]
    DIRECTION INPUT ;
    USE SIGNAL ;
    PORT
      LAYER M5 ;
        RECT  177.408 0 177.432 0.084 ;
    END
  END xs_q1[10]
  PIN xs_q1[110]
    DIRECTION INPUT ;
    USE SIGNAL ;
    PORT
      LAYER M5 ;
        RECT  187.008 0 187.032 0.084 ;
    END
  END xs_q1[110]
  PIN xs_q1[111]
    DIRECTION INPUT ;
    USE SIGNAL ;
    PORT
      LAYER M5 ;
        RECT  187.104 0 187.128 0.084 ;
    END
  END xs_q1[111]
  PIN xs_q1[112]
    DIRECTION INPUT ;
    USE SIGNAL ;
    PORT
      LAYER M5 ;
        RECT  187.2 0 187.224 0.084 ;
    END
  END xs_q1[112]
  PIN xs_q1[113]
    DIRECTION INPUT ;
    USE SIGNAL ;
    PORT
      LAYER M5 ;
        RECT  187.296 0 187.32 0.084 ;
    END
  END xs_q1[113]
  PIN xs_q1[114]
    DIRECTION INPUT ;
    USE SIGNAL ;
    PORT
      LAYER M5 ;
        RECT  187.392 0 187.416 0.084 ;
    END
  END xs_q1[114]
  PIN xs_q1[115]
    DIRECTION INPUT ;
    USE SIGNAL ;
    PORT
      LAYER M5 ;
        RECT  187.488 0 187.512 0.084 ;
    END
  END xs_q1[115]
  PIN xs_q1[116]
    DIRECTION INPUT ;
    USE SIGNAL ;
    PORT
      LAYER M5 ;
        RECT  187.584 0 187.608 0.084 ;
    END
  END xs_q1[116]
  PIN xs_q1[117]
    DIRECTION INPUT ;
    USE SIGNAL ;
    PORT
      LAYER M5 ;
        RECT  187.68 0 187.704 0.084 ;
    END
  END xs_q1[117]
  PIN xs_q1[118]
    DIRECTION INPUT ;
    USE SIGNAL ;
    PORT
      LAYER M5 ;
        RECT  187.776 0 187.8 0.084 ;
    END
  END xs_q1[118]
  PIN xs_q1[119]
    DIRECTION INPUT ;
    USE SIGNAL ;
    PORT
      LAYER M5 ;
        RECT  187.872 0 187.896 0.084 ;
    END
  END xs_q1[119]
  PIN xs_q1[11]
    DIRECTION INPUT ;
    USE SIGNAL ;
    PORT
      LAYER M5 ;
        RECT  177.504 0 177.528 0.084 ;
    END
  END xs_q1[11]
  PIN xs_q1[120]
    DIRECTION INPUT ;
    USE SIGNAL ;
    PORT
      LAYER M5 ;
        RECT  187.968 0 187.992 0.084 ;
    END
  END xs_q1[120]
  PIN xs_q1[121]
    DIRECTION INPUT ;
    USE SIGNAL ;
    PORT
      LAYER M5 ;
        RECT  188.064 0 188.088 0.084 ;
    END
  END xs_q1[121]
  PIN xs_q1[122]
    DIRECTION INPUT ;
    USE SIGNAL ;
    PORT
      LAYER M5 ;
        RECT  188.16 0 188.184 0.084 ;
    END
  END xs_q1[122]
  PIN xs_q1[123]
    DIRECTION INPUT ;
    USE SIGNAL ;
    PORT
      LAYER M5 ;
        RECT  188.256 0 188.28 0.084 ;
    END
  END xs_q1[123]
  PIN xs_q1[124]
    DIRECTION INPUT ;
    USE SIGNAL ;
    PORT
      LAYER M5 ;
        RECT  188.352 0 188.376 0.084 ;
    END
  END xs_q1[124]
  PIN xs_q1[125]
    DIRECTION INPUT ;
    USE SIGNAL ;
    PORT
      LAYER M5 ;
        RECT  188.448 0 188.472 0.084 ;
    END
  END xs_q1[125]
  PIN xs_q1[126]
    DIRECTION INPUT ;
    USE SIGNAL ;
    PORT
      LAYER M5 ;
        RECT  188.544 0 188.568 0.084 ;
    END
  END xs_q1[126]
  PIN xs_q1[127]
    DIRECTION INPUT ;
    USE SIGNAL ;
    PORT
      LAYER M5 ;
        RECT  188.64 0 188.664 0.084 ;
    END
  END xs_q1[127]
  PIN xs_q1[128]
    DIRECTION INPUT ;
    USE SIGNAL ;
    PORT
      LAYER M5 ;
        RECT  188.736 0 188.76 0.084 ;
    END
  END xs_q1[128]
  PIN xs_q1[129]
    DIRECTION INPUT ;
    USE SIGNAL ;
    PORT
      LAYER M5 ;
        RECT  188.832 0 188.856 0.084 ;
    END
  END xs_q1[129]
  PIN xs_q1[12]
    DIRECTION INPUT ;
    USE SIGNAL ;
    PORT
      LAYER M5 ;
        RECT  177.6 0 177.624 0.084 ;
    END
  END xs_q1[12]
  PIN xs_q1[130]
    DIRECTION INPUT ;
    USE SIGNAL ;
    PORT
      LAYER M5 ;
        RECT  188.928 0 188.952 0.084 ;
    END
  END xs_q1[130]
  PIN xs_q1[131]
    DIRECTION INPUT ;
    USE SIGNAL ;
    PORT
      LAYER M5 ;
        RECT  189.024 0 189.048 0.084 ;
    END
  END xs_q1[131]
  PIN xs_q1[132]
    DIRECTION INPUT ;
    USE SIGNAL ;
    PORT
      LAYER M5 ;
        RECT  189.12 0 189.144 0.084 ;
    END
  END xs_q1[132]
  PIN xs_q1[133]
    DIRECTION INPUT ;
    USE SIGNAL ;
    PORT
      LAYER M5 ;
        RECT  189.216 0 189.24 0.084 ;
    END
  END xs_q1[133]
  PIN xs_q1[134]
    DIRECTION INPUT ;
    USE SIGNAL ;
    PORT
      LAYER M5 ;
        RECT  189.312 0 189.336 0.084 ;
    END
  END xs_q1[134]
  PIN xs_q1[135]
    DIRECTION INPUT ;
    USE SIGNAL ;
    PORT
      LAYER M5 ;
        RECT  189.408 0 189.432 0.084 ;
    END
  END xs_q1[135]
  PIN xs_q1[136]
    DIRECTION INPUT ;
    USE SIGNAL ;
    PORT
      LAYER M5 ;
        RECT  189.504 0 189.528 0.084 ;
    END
  END xs_q1[136]
  PIN xs_q1[137]
    DIRECTION INPUT ;
    USE SIGNAL ;
    PORT
      LAYER M5 ;
        RECT  189.6 0 189.624 0.084 ;
    END
  END xs_q1[137]
  PIN xs_q1[138]
    DIRECTION INPUT ;
    USE SIGNAL ;
    PORT
      LAYER M5 ;
        RECT  189.696 0 189.72 0.084 ;
    END
  END xs_q1[138]
  PIN xs_q1[139]
    DIRECTION INPUT ;
    USE SIGNAL ;
    PORT
      LAYER M5 ;
        RECT  189.792 0 189.816 0.084 ;
    END
  END xs_q1[139]
  PIN xs_q1[13]
    DIRECTION INPUT ;
    USE SIGNAL ;
    PORT
      LAYER M5 ;
        RECT  177.696 0 177.72 0.084 ;
    END
  END xs_q1[13]
  PIN xs_q1[140]
    DIRECTION INPUT ;
    USE SIGNAL ;
    PORT
      LAYER M5 ;
        RECT  189.888 0 189.912 0.084 ;
    END
  END xs_q1[140]
  PIN xs_q1[141]
    DIRECTION INPUT ;
    USE SIGNAL ;
    PORT
      LAYER M5 ;
        RECT  189.984 0 190.008 0.084 ;
    END
  END xs_q1[141]
  PIN xs_q1[142]
    DIRECTION INPUT ;
    USE SIGNAL ;
    PORT
      LAYER M5 ;
        RECT  190.08 0 190.104 0.084 ;
    END
  END xs_q1[142]
  PIN xs_q1[143]
    DIRECTION INPUT ;
    USE SIGNAL ;
    PORT
      LAYER M5 ;
        RECT  190.176 0 190.2 0.084 ;
    END
  END xs_q1[143]
  PIN xs_q1[144]
    DIRECTION INPUT ;
    USE SIGNAL ;
    PORT
      LAYER M5 ;
        RECT  190.272 0 190.296 0.084 ;
    END
  END xs_q1[144]
  PIN xs_q1[145]
    DIRECTION INPUT ;
    USE SIGNAL ;
    PORT
      LAYER M5 ;
        RECT  190.368 0 190.392 0.084 ;
    END
  END xs_q1[145]
  PIN xs_q1[146]
    DIRECTION INPUT ;
    USE SIGNAL ;
    PORT
      LAYER M5 ;
        RECT  190.464 0 190.488 0.084 ;
    END
  END xs_q1[146]
  PIN xs_q1[147]
    DIRECTION INPUT ;
    USE SIGNAL ;
    PORT
      LAYER M5 ;
        RECT  190.56 0 190.584 0.084 ;
    END
  END xs_q1[147]
  PIN xs_q1[148]
    DIRECTION INPUT ;
    USE SIGNAL ;
    PORT
      LAYER M5 ;
        RECT  190.656 0 190.68 0.084 ;
    END
  END xs_q1[148]
  PIN xs_q1[149]
    DIRECTION INPUT ;
    USE SIGNAL ;
    PORT
      LAYER M5 ;
        RECT  190.752 0 190.776 0.084 ;
    END
  END xs_q1[149]
  PIN xs_q1[14]
    DIRECTION INPUT ;
    USE SIGNAL ;
    PORT
      LAYER M5 ;
        RECT  177.792 0 177.816 0.084 ;
    END
  END xs_q1[14]
  PIN xs_q1[150]
    DIRECTION INPUT ;
    USE SIGNAL ;
    PORT
      LAYER M5 ;
        RECT  190.848 0 190.872 0.084 ;
    END
  END xs_q1[150]
  PIN xs_q1[151]
    DIRECTION INPUT ;
    USE SIGNAL ;
    PORT
      LAYER M5 ;
        RECT  190.944 0 190.968 0.084 ;
    END
  END xs_q1[151]
  PIN xs_q1[152]
    DIRECTION INPUT ;
    USE SIGNAL ;
    PORT
      LAYER M5 ;
        RECT  191.04 0 191.064 0.084 ;
    END
  END xs_q1[152]
  PIN xs_q1[153]
    DIRECTION INPUT ;
    USE SIGNAL ;
    PORT
      LAYER M5 ;
        RECT  191.136 0 191.16 0.084 ;
    END
  END xs_q1[153]
  PIN xs_q1[154]
    DIRECTION INPUT ;
    USE SIGNAL ;
    PORT
      LAYER M5 ;
        RECT  191.232 0 191.256 0.084 ;
    END
  END xs_q1[154]
  PIN xs_q1[155]
    DIRECTION INPUT ;
    USE SIGNAL ;
    PORT
      LAYER M5 ;
        RECT  191.328 0 191.352 0.084 ;
    END
  END xs_q1[155]
  PIN xs_q1[156]
    DIRECTION INPUT ;
    USE SIGNAL ;
    PORT
      LAYER M5 ;
        RECT  191.424 0 191.448 0.084 ;
    END
  END xs_q1[156]
  PIN xs_q1[157]
    DIRECTION INPUT ;
    USE SIGNAL ;
    PORT
      LAYER M5 ;
        RECT  191.52 0 191.544 0.084 ;
    END
  END xs_q1[157]
  PIN xs_q1[158]
    DIRECTION INPUT ;
    USE SIGNAL ;
    PORT
      LAYER M5 ;
        RECT  191.616 0 191.64 0.084 ;
    END
  END xs_q1[158]
  PIN xs_q1[159]
    DIRECTION INPUT ;
    USE SIGNAL ;
    PORT
      LAYER M5 ;
        RECT  191.712 0 191.736 0.084 ;
    END
  END xs_q1[159]
  PIN xs_q1[15]
    DIRECTION INPUT ;
    USE SIGNAL ;
    PORT
      LAYER M5 ;
        RECT  177.888 0 177.912 0.084 ;
    END
  END xs_q1[15]
  PIN xs_q1[160]
    DIRECTION INPUT ;
    USE SIGNAL ;
    PORT
      LAYER M5 ;
        RECT  191.808 0 191.832 0.084 ;
    END
  END xs_q1[160]
  PIN xs_q1[161]
    DIRECTION INPUT ;
    USE SIGNAL ;
    PORT
      LAYER M5 ;
        RECT  191.904 0 191.928 0.084 ;
    END
  END xs_q1[161]
  PIN xs_q1[162]
    DIRECTION INPUT ;
    USE SIGNAL ;
    PORT
      LAYER M5 ;
        RECT  192 0 192.024 0.084 ;
    END
  END xs_q1[162]
  PIN xs_q1[163]
    DIRECTION INPUT ;
    USE SIGNAL ;
    PORT
      LAYER M5 ;
        RECT  192.096 0 192.12 0.084 ;
    END
  END xs_q1[163]
  PIN xs_q1[164]
    DIRECTION INPUT ;
    USE SIGNAL ;
    PORT
      LAYER M5 ;
        RECT  192.192 0 192.216 0.084 ;
    END
  END xs_q1[164]
  PIN xs_q1[165]
    DIRECTION INPUT ;
    USE SIGNAL ;
    PORT
      LAYER M5 ;
        RECT  192.288 0 192.312 0.084 ;
    END
  END xs_q1[165]
  PIN xs_q1[166]
    DIRECTION INPUT ;
    USE SIGNAL ;
    PORT
      LAYER M5 ;
        RECT  192.384 0 192.408 0.084 ;
    END
  END xs_q1[166]
  PIN xs_q1[167]
    DIRECTION INPUT ;
    USE SIGNAL ;
    PORT
      LAYER M5 ;
        RECT  192.48 0 192.504 0.084 ;
    END
  END xs_q1[167]
  PIN xs_q1[168]
    DIRECTION INPUT ;
    USE SIGNAL ;
    PORT
      LAYER M5 ;
        RECT  192.576 0 192.6 0.084 ;
    END
  END xs_q1[168]
  PIN xs_q1[169]
    DIRECTION INPUT ;
    USE SIGNAL ;
    PORT
      LAYER M5 ;
        RECT  192.672 0 192.696 0.084 ;
    END
  END xs_q1[169]
  PIN xs_q1[16]
    DIRECTION INPUT ;
    USE SIGNAL ;
    PORT
      LAYER M5 ;
        RECT  177.984 0 178.008 0.084 ;
    END
  END xs_q1[16]
  PIN xs_q1[170]
    DIRECTION INPUT ;
    USE SIGNAL ;
    PORT
      LAYER M5 ;
        RECT  192.768 0 192.792 0.084 ;
    END
  END xs_q1[170]
  PIN xs_q1[171]
    DIRECTION INPUT ;
    USE SIGNAL ;
    PORT
      LAYER M5 ;
        RECT  192.864 0 192.888 0.084 ;
    END
  END xs_q1[171]
  PIN xs_q1[172]
    DIRECTION INPUT ;
    USE SIGNAL ;
    PORT
      LAYER M5 ;
        RECT  192.96 0 192.984 0.084 ;
    END
  END xs_q1[172]
  PIN xs_q1[173]
    DIRECTION INPUT ;
    USE SIGNAL ;
    PORT
      LAYER M5 ;
        RECT  193.056 0 193.08 0.084 ;
    END
  END xs_q1[173]
  PIN xs_q1[174]
    DIRECTION INPUT ;
    USE SIGNAL ;
    PORT
      LAYER M5 ;
        RECT  193.152 0 193.176 0.084 ;
    END
  END xs_q1[174]
  PIN xs_q1[175]
    DIRECTION INPUT ;
    USE SIGNAL ;
    PORT
      LAYER M5 ;
        RECT  193.248 0 193.272 0.084 ;
    END
  END xs_q1[175]
  PIN xs_q1[176]
    DIRECTION INPUT ;
    USE SIGNAL ;
    PORT
      LAYER M5 ;
        RECT  193.344 0 193.368 0.084 ;
    END
  END xs_q1[176]
  PIN xs_q1[177]
    DIRECTION INPUT ;
    USE SIGNAL ;
    PORT
      LAYER M5 ;
        RECT  193.44 0 193.464 0.084 ;
    END
  END xs_q1[177]
  PIN xs_q1[178]
    DIRECTION INPUT ;
    USE SIGNAL ;
    PORT
      LAYER M5 ;
        RECT  193.536 0 193.56 0.084 ;
    END
  END xs_q1[178]
  PIN xs_q1[179]
    DIRECTION INPUT ;
    USE SIGNAL ;
    PORT
      LAYER M5 ;
        RECT  193.632 0 193.656 0.084 ;
    END
  END xs_q1[179]
  PIN xs_q1[17]
    DIRECTION INPUT ;
    USE SIGNAL ;
    PORT
      LAYER M5 ;
        RECT  178.08 0 178.104 0.084 ;
    END
  END xs_q1[17]
  PIN xs_q1[180]
    DIRECTION INPUT ;
    USE SIGNAL ;
    PORT
      LAYER M5 ;
        RECT  193.728 0 193.752 0.084 ;
    END
  END xs_q1[180]
  PIN xs_q1[181]
    DIRECTION INPUT ;
    USE SIGNAL ;
    PORT
      LAYER M5 ;
        RECT  193.824 0 193.848 0.084 ;
    END
  END xs_q1[181]
  PIN xs_q1[182]
    DIRECTION INPUT ;
    USE SIGNAL ;
    PORT
      LAYER M5 ;
        RECT  193.92 0 193.944 0.084 ;
    END
  END xs_q1[182]
  PIN xs_q1[183]
    DIRECTION INPUT ;
    USE SIGNAL ;
    PORT
      LAYER M5 ;
        RECT  194.016 0 194.04 0.084 ;
    END
  END xs_q1[183]
  PIN xs_q1[184]
    DIRECTION INPUT ;
    USE SIGNAL ;
    PORT
      LAYER M5 ;
        RECT  194.112 0 194.136 0.084 ;
    END
  END xs_q1[184]
  PIN xs_q1[185]
    DIRECTION INPUT ;
    USE SIGNAL ;
    PORT
      LAYER M5 ;
        RECT  194.208 0 194.232 0.084 ;
    END
  END xs_q1[185]
  PIN xs_q1[186]
    DIRECTION INPUT ;
    USE SIGNAL ;
    PORT
      LAYER M5 ;
        RECT  194.304 0 194.328 0.084 ;
    END
  END xs_q1[186]
  PIN xs_q1[187]
    DIRECTION INPUT ;
    USE SIGNAL ;
    PORT
      LAYER M5 ;
        RECT  194.4 0 194.424 0.084 ;
    END
  END xs_q1[187]
  PIN xs_q1[188]
    DIRECTION INPUT ;
    USE SIGNAL ;
    PORT
      LAYER M5 ;
        RECT  194.496 0 194.52 0.084 ;
    END
  END xs_q1[188]
  PIN xs_q1[189]
    DIRECTION INPUT ;
    USE SIGNAL ;
    PORT
      LAYER M5 ;
        RECT  194.592 0 194.616 0.084 ;
    END
  END xs_q1[189]
  PIN xs_q1[18]
    DIRECTION INPUT ;
    USE SIGNAL ;
    PORT
      LAYER M5 ;
        RECT  178.176 0 178.2 0.084 ;
    END
  END xs_q1[18]
  PIN xs_q1[190]
    DIRECTION INPUT ;
    USE SIGNAL ;
    PORT
      LAYER M5 ;
        RECT  194.688 0 194.712 0.084 ;
    END
  END xs_q1[190]
  PIN xs_q1[191]
    DIRECTION INPUT ;
    USE SIGNAL ;
    PORT
      LAYER M5 ;
        RECT  194.784 0 194.808 0.084 ;
    END
  END xs_q1[191]
  PIN xs_q1[192]
    DIRECTION INPUT ;
    USE SIGNAL ;
    PORT
      LAYER M5 ;
        RECT  194.88 0 194.904 0.084 ;
    END
  END xs_q1[192]
  PIN xs_q1[193]
    DIRECTION INPUT ;
    USE SIGNAL ;
    PORT
      LAYER M5 ;
        RECT  194.976 0 195 0.084 ;
    END
  END xs_q1[193]
  PIN xs_q1[194]
    DIRECTION INPUT ;
    USE SIGNAL ;
    PORT
      LAYER M5 ;
        RECT  195.072 0 195.096 0.084 ;
    END
  END xs_q1[194]
  PIN xs_q1[195]
    DIRECTION INPUT ;
    USE SIGNAL ;
    PORT
      LAYER M5 ;
        RECT  195.168 0 195.192 0.084 ;
    END
  END xs_q1[195]
  PIN xs_q1[196]
    DIRECTION INPUT ;
    USE SIGNAL ;
    PORT
      LAYER M5 ;
        RECT  195.264 0 195.288 0.084 ;
    END
  END xs_q1[196]
  PIN xs_q1[197]
    DIRECTION INPUT ;
    USE SIGNAL ;
    PORT
      LAYER M5 ;
        RECT  195.36 0 195.384 0.084 ;
    END
  END xs_q1[197]
  PIN xs_q1[198]
    DIRECTION INPUT ;
    USE SIGNAL ;
    PORT
      LAYER M5 ;
        RECT  195.456 0 195.48 0.084 ;
    END
  END xs_q1[198]
  PIN xs_q1[199]
    DIRECTION INPUT ;
    USE SIGNAL ;
    PORT
      LAYER M5 ;
        RECT  195.552 0 195.576 0.084 ;
    END
  END xs_q1[199]
  PIN xs_q1[19]
    DIRECTION INPUT ;
    USE SIGNAL ;
    PORT
      LAYER M5 ;
        RECT  178.272 0 178.296 0.084 ;
    END
  END xs_q1[19]
  PIN xs_q1[1]
    DIRECTION INPUT ;
    USE SIGNAL ;
    PORT
      LAYER M5 ;
        RECT  176.544 0 176.568 0.084 ;
    END
  END xs_q1[1]
  PIN xs_q1[200]
    DIRECTION INPUT ;
    USE SIGNAL ;
    PORT
      LAYER M5 ;
        RECT  195.648 0 195.672 0.084 ;
    END
  END xs_q1[200]
  PIN xs_q1[201]
    DIRECTION INPUT ;
    USE SIGNAL ;
    PORT
      LAYER M5 ;
        RECT  195.744 0 195.768 0.084 ;
    END
  END xs_q1[201]
  PIN xs_q1[202]
    DIRECTION INPUT ;
    USE SIGNAL ;
    PORT
      LAYER M5 ;
        RECT  195.84 0 195.864 0.084 ;
    END
  END xs_q1[202]
  PIN xs_q1[203]
    DIRECTION INPUT ;
    USE SIGNAL ;
    PORT
      LAYER M5 ;
        RECT  195.936 0 195.96 0.084 ;
    END
  END xs_q1[203]
  PIN xs_q1[204]
    DIRECTION INPUT ;
    USE SIGNAL ;
    PORT
      LAYER M5 ;
        RECT  196.032 0 196.056 0.084 ;
    END
  END xs_q1[204]
  PIN xs_q1[205]
    DIRECTION INPUT ;
    USE SIGNAL ;
    PORT
      LAYER M5 ;
        RECT  196.128 0 196.152 0.084 ;
    END
  END xs_q1[205]
  PIN xs_q1[206]
    DIRECTION INPUT ;
    USE SIGNAL ;
    PORT
      LAYER M5 ;
        RECT  196.224 0 196.248 0.084 ;
    END
  END xs_q1[206]
  PIN xs_q1[207]
    DIRECTION INPUT ;
    USE SIGNAL ;
    PORT
      LAYER M5 ;
        RECT  196.32 0 196.344 0.084 ;
    END
  END xs_q1[207]
  PIN xs_q1[208]
    DIRECTION INPUT ;
    USE SIGNAL ;
    PORT
      LAYER M5 ;
        RECT  196.416 0 196.44 0.084 ;
    END
  END xs_q1[208]
  PIN xs_q1[209]
    DIRECTION INPUT ;
    USE SIGNAL ;
    PORT
      LAYER M5 ;
        RECT  196.512 0 196.536 0.084 ;
    END
  END xs_q1[209]
  PIN xs_q1[20]
    DIRECTION INPUT ;
    USE SIGNAL ;
    PORT
      LAYER M5 ;
        RECT  178.368 0 178.392 0.084 ;
    END
  END xs_q1[20]
  PIN xs_q1[210]
    DIRECTION INPUT ;
    USE SIGNAL ;
    PORT
      LAYER M5 ;
        RECT  196.608 0 196.632 0.084 ;
    END
  END xs_q1[210]
  PIN xs_q1[211]
    DIRECTION INPUT ;
    USE SIGNAL ;
    PORT
      LAYER M5 ;
        RECT  196.704 0 196.728 0.084 ;
    END
  END xs_q1[211]
  PIN xs_q1[212]
    DIRECTION INPUT ;
    USE SIGNAL ;
    PORT
      LAYER M5 ;
        RECT  196.8 0 196.824 0.084 ;
    END
  END xs_q1[212]
  PIN xs_q1[213]
    DIRECTION INPUT ;
    USE SIGNAL ;
    PORT
      LAYER M5 ;
        RECT  196.896 0 196.92 0.084 ;
    END
  END xs_q1[213]
  PIN xs_q1[214]
    DIRECTION INPUT ;
    USE SIGNAL ;
    PORT
      LAYER M5 ;
        RECT  196.992 0 197.016 0.084 ;
    END
  END xs_q1[214]
  PIN xs_q1[215]
    DIRECTION INPUT ;
    USE SIGNAL ;
    PORT
      LAYER M5 ;
        RECT  197.088 0 197.112 0.084 ;
    END
  END xs_q1[215]
  PIN xs_q1[216]
    DIRECTION INPUT ;
    USE SIGNAL ;
    PORT
      LAYER M5 ;
        RECT  197.184 0 197.208 0.084 ;
    END
  END xs_q1[216]
  PIN xs_q1[217]
    DIRECTION INPUT ;
    USE SIGNAL ;
    PORT
      LAYER M5 ;
        RECT  197.28 0 197.304 0.084 ;
    END
  END xs_q1[217]
  PIN xs_q1[218]
    DIRECTION INPUT ;
    USE SIGNAL ;
    PORT
      LAYER M5 ;
        RECT  197.376 0 197.4 0.084 ;
    END
  END xs_q1[218]
  PIN xs_q1[219]
    DIRECTION INPUT ;
    USE SIGNAL ;
    PORT
      LAYER M5 ;
        RECT  197.472 0 197.496 0.084 ;
    END
  END xs_q1[219]
  PIN xs_q1[21]
    DIRECTION INPUT ;
    USE SIGNAL ;
    PORT
      LAYER M5 ;
        RECT  178.464 0 178.488 0.084 ;
    END
  END xs_q1[21]
  PIN xs_q1[220]
    DIRECTION INPUT ;
    USE SIGNAL ;
    PORT
      LAYER M5 ;
        RECT  197.568 0 197.592 0.084 ;
    END
  END xs_q1[220]
  PIN xs_q1[221]
    DIRECTION INPUT ;
    USE SIGNAL ;
    PORT
      LAYER M5 ;
        RECT  197.664 0 197.688 0.084 ;
    END
  END xs_q1[221]
  PIN xs_q1[222]
    DIRECTION INPUT ;
    USE SIGNAL ;
    PORT
      LAYER M5 ;
        RECT  197.76 0 197.784 0.084 ;
    END
  END xs_q1[222]
  PIN xs_q1[223]
    DIRECTION INPUT ;
    USE SIGNAL ;
    PORT
      LAYER M5 ;
        RECT  197.856 0 197.88 0.084 ;
    END
  END xs_q1[223]
  PIN xs_q1[224]
    DIRECTION INPUT ;
    USE SIGNAL ;
    PORT
      LAYER M5 ;
        RECT  197.952 0 197.976 0.084 ;
    END
  END xs_q1[224]
  PIN xs_q1[225]
    DIRECTION INPUT ;
    USE SIGNAL ;
    PORT
      LAYER M5 ;
        RECT  198.048 0 198.072 0.084 ;
    END
  END xs_q1[225]
  PIN xs_q1[226]
    DIRECTION INPUT ;
    USE SIGNAL ;
    PORT
      LAYER M5 ;
        RECT  198.144 0 198.168 0.084 ;
    END
  END xs_q1[226]
  PIN xs_q1[227]
    DIRECTION INPUT ;
    USE SIGNAL ;
    PORT
      LAYER M5 ;
        RECT  198.24 0 198.264 0.084 ;
    END
  END xs_q1[227]
  PIN xs_q1[228]
    DIRECTION INPUT ;
    USE SIGNAL ;
    PORT
      LAYER M5 ;
        RECT  198.336 0 198.36 0.084 ;
    END
  END xs_q1[228]
  PIN xs_q1[229]
    DIRECTION INPUT ;
    USE SIGNAL ;
    PORT
      LAYER M5 ;
        RECT  198.432 0 198.456 0.084 ;
    END
  END xs_q1[229]
  PIN xs_q1[22]
    DIRECTION INPUT ;
    USE SIGNAL ;
    PORT
      LAYER M5 ;
        RECT  178.56 0 178.584 0.084 ;
    END
  END xs_q1[22]
  PIN xs_q1[230]
    DIRECTION INPUT ;
    USE SIGNAL ;
    PORT
      LAYER M5 ;
        RECT  198.528 0 198.552 0.084 ;
    END
  END xs_q1[230]
  PIN xs_q1[231]
    DIRECTION INPUT ;
    USE SIGNAL ;
    PORT
      LAYER M5 ;
        RECT  198.624 0 198.648 0.084 ;
    END
  END xs_q1[231]
  PIN xs_q1[232]
    DIRECTION INPUT ;
    USE SIGNAL ;
    PORT
      LAYER M5 ;
        RECT  198.72 0 198.744 0.084 ;
    END
  END xs_q1[232]
  PIN xs_q1[233]
    DIRECTION INPUT ;
    USE SIGNAL ;
    PORT
      LAYER M5 ;
        RECT  198.816 0 198.84 0.084 ;
    END
  END xs_q1[233]
  PIN xs_q1[234]
    DIRECTION INPUT ;
    USE SIGNAL ;
    PORT
      LAYER M5 ;
        RECT  198.912 0 198.936 0.084 ;
    END
  END xs_q1[234]
  PIN xs_q1[235]
    DIRECTION INPUT ;
    USE SIGNAL ;
    PORT
      LAYER M5 ;
        RECT  199.008 0 199.032 0.084 ;
    END
  END xs_q1[235]
  PIN xs_q1[236]
    DIRECTION INPUT ;
    USE SIGNAL ;
    PORT
      LAYER M5 ;
        RECT  199.104 0 199.128 0.084 ;
    END
  END xs_q1[236]
  PIN xs_q1[237]
    DIRECTION INPUT ;
    USE SIGNAL ;
    PORT
      LAYER M5 ;
        RECT  199.2 0 199.224 0.084 ;
    END
  END xs_q1[237]
  PIN xs_q1[238]
    DIRECTION INPUT ;
    USE SIGNAL ;
    PORT
      LAYER M5 ;
        RECT  199.296 0 199.32 0.084 ;
    END
  END xs_q1[238]
  PIN xs_q1[239]
    DIRECTION INPUT ;
    USE SIGNAL ;
    PORT
      LAYER M5 ;
        RECT  199.392 0 199.416 0.084 ;
    END
  END xs_q1[239]
  PIN xs_q1[23]
    DIRECTION INPUT ;
    USE SIGNAL ;
    PORT
      LAYER M5 ;
        RECT  178.656 0 178.68 0.084 ;
    END
  END xs_q1[23]
  PIN xs_q1[240]
    DIRECTION INPUT ;
    USE SIGNAL ;
    PORT
      LAYER M5 ;
        RECT  199.488 0 199.512 0.084 ;
    END
  END xs_q1[240]
  PIN xs_q1[241]
    DIRECTION INPUT ;
    USE SIGNAL ;
    PORT
      LAYER M5 ;
        RECT  199.584 0 199.608 0.084 ;
    END
  END xs_q1[241]
  PIN xs_q1[242]
    DIRECTION INPUT ;
    USE SIGNAL ;
    PORT
      LAYER M5 ;
        RECT  199.68 0 199.704 0.084 ;
    END
  END xs_q1[242]
  PIN xs_q1[243]
    DIRECTION INPUT ;
    USE SIGNAL ;
    PORT
      LAYER M5 ;
        RECT  199.776 0 199.8 0.084 ;
    END
  END xs_q1[243]
  PIN xs_q1[244]
    DIRECTION INPUT ;
    USE SIGNAL ;
    PORT
      LAYER M5 ;
        RECT  199.872 0 199.896 0.084 ;
    END
  END xs_q1[244]
  PIN xs_q1[245]
    DIRECTION INPUT ;
    USE SIGNAL ;
    PORT
      LAYER M5 ;
        RECT  199.968 0 199.992 0.084 ;
    END
  END xs_q1[245]
  PIN xs_q1[246]
    DIRECTION INPUT ;
    USE SIGNAL ;
    PORT
      LAYER M5 ;
        RECT  200.064 0 200.088 0.084 ;
    END
  END xs_q1[246]
  PIN xs_q1[247]
    DIRECTION INPUT ;
    USE SIGNAL ;
    PORT
      LAYER M5 ;
        RECT  200.16 0 200.184 0.084 ;
    END
  END xs_q1[247]
  PIN xs_q1[248]
    DIRECTION INPUT ;
    USE SIGNAL ;
    PORT
      LAYER M5 ;
        RECT  200.256 0 200.28 0.084 ;
    END
  END xs_q1[248]
  PIN xs_q1[249]
    DIRECTION INPUT ;
    USE SIGNAL ;
    PORT
      LAYER M5 ;
        RECT  200.352 0 200.376 0.084 ;
    END
  END xs_q1[249]
  PIN xs_q1[24]
    DIRECTION INPUT ;
    USE SIGNAL ;
    PORT
      LAYER M5 ;
        RECT  178.752 0 178.776 0.084 ;
    END
  END xs_q1[24]
  PIN xs_q1[250]
    DIRECTION INPUT ;
    USE SIGNAL ;
    PORT
      LAYER M5 ;
        RECT  200.448 0 200.472 0.084 ;
    END
  END xs_q1[250]
  PIN xs_q1[251]
    DIRECTION INPUT ;
    USE SIGNAL ;
    PORT
      LAYER M5 ;
        RECT  200.544 0 200.568 0.084 ;
    END
  END xs_q1[251]
  PIN xs_q1[252]
    DIRECTION INPUT ;
    USE SIGNAL ;
    PORT
      LAYER M5 ;
        RECT  200.64 0 200.664 0.084 ;
    END
  END xs_q1[252]
  PIN xs_q1[253]
    DIRECTION INPUT ;
    USE SIGNAL ;
    PORT
      LAYER M5 ;
        RECT  200.736 0 200.76 0.084 ;
    END
  END xs_q1[253]
  PIN xs_q1[254]
    DIRECTION INPUT ;
    USE SIGNAL ;
    PORT
      LAYER M5 ;
        RECT  200.832 0 200.856 0.084 ;
    END
  END xs_q1[254]
  PIN xs_q1[255]
    DIRECTION INPUT ;
    USE SIGNAL ;
    PORT
      LAYER M5 ;
        RECT  200.928 0 200.952 0.084 ;
    END
  END xs_q1[255]
  PIN xs_q1[25]
    DIRECTION INPUT ;
    USE SIGNAL ;
    PORT
      LAYER M5 ;
        RECT  178.848 0 178.872 0.084 ;
    END
  END xs_q1[25]
  PIN xs_q1[26]
    DIRECTION INPUT ;
    USE SIGNAL ;
    PORT
      LAYER M5 ;
        RECT  178.944 0 178.968 0.084 ;
    END
  END xs_q1[26]
  PIN xs_q1[27]
    DIRECTION INPUT ;
    USE SIGNAL ;
    PORT
      LAYER M5 ;
        RECT  179.04 0 179.064 0.084 ;
    END
  END xs_q1[27]
  PIN xs_q1[28]
    DIRECTION INPUT ;
    USE SIGNAL ;
    PORT
      LAYER M5 ;
        RECT  179.136 0 179.16 0.084 ;
    END
  END xs_q1[28]
  PIN xs_q1[29]
    DIRECTION INPUT ;
    USE SIGNAL ;
    PORT
      LAYER M5 ;
        RECT  179.232 0 179.256 0.084 ;
    END
  END xs_q1[29]
  PIN xs_q1[2]
    DIRECTION INPUT ;
    USE SIGNAL ;
    PORT
      LAYER M5 ;
        RECT  176.64 0 176.664 0.084 ;
    END
  END xs_q1[2]
  PIN xs_q1[30]
    DIRECTION INPUT ;
    USE SIGNAL ;
    PORT
      LAYER M5 ;
        RECT  179.328 0 179.352 0.084 ;
    END
  END xs_q1[30]
  PIN xs_q1[31]
    DIRECTION INPUT ;
    USE SIGNAL ;
    PORT
      LAYER M5 ;
        RECT  179.424 0 179.448 0.084 ;
    END
  END xs_q1[31]
  PIN xs_q1[32]
    DIRECTION INPUT ;
    USE SIGNAL ;
    PORT
      LAYER M5 ;
        RECT  179.52 0 179.544 0.084 ;
    END
  END xs_q1[32]
  PIN xs_q1[33]
    DIRECTION INPUT ;
    USE SIGNAL ;
    PORT
      LAYER M5 ;
        RECT  179.616 0 179.64 0.084 ;
    END
  END xs_q1[33]
  PIN xs_q1[34]
    DIRECTION INPUT ;
    USE SIGNAL ;
    PORT
      LAYER M5 ;
        RECT  179.712 0 179.736 0.084 ;
    END
  END xs_q1[34]
  PIN xs_q1[35]
    DIRECTION INPUT ;
    USE SIGNAL ;
    PORT
      LAYER M5 ;
        RECT  179.808 0 179.832 0.084 ;
    END
  END xs_q1[35]
  PIN xs_q1[36]
    DIRECTION INPUT ;
    USE SIGNAL ;
    PORT
      LAYER M5 ;
        RECT  179.904 0 179.928 0.084 ;
    END
  END xs_q1[36]
  PIN xs_q1[37]
    DIRECTION INPUT ;
    USE SIGNAL ;
    PORT
      LAYER M5 ;
        RECT  180 0 180.024 0.084 ;
    END
  END xs_q1[37]
  PIN xs_q1[38]
    DIRECTION INPUT ;
    USE SIGNAL ;
    PORT
      LAYER M5 ;
        RECT  180.096 0 180.12 0.084 ;
    END
  END xs_q1[38]
  PIN xs_q1[39]
    DIRECTION INPUT ;
    USE SIGNAL ;
    PORT
      LAYER M5 ;
        RECT  180.192 0 180.216 0.084 ;
    END
  END xs_q1[39]
  PIN xs_q1[3]
    DIRECTION INPUT ;
    USE SIGNAL ;
    PORT
      LAYER M5 ;
        RECT  176.736 0 176.76 0.084 ;
    END
  END xs_q1[3]
  PIN xs_q1[40]
    DIRECTION INPUT ;
    USE SIGNAL ;
    PORT
      LAYER M5 ;
        RECT  180.288 0 180.312 0.084 ;
    END
  END xs_q1[40]
  PIN xs_q1[41]
    DIRECTION INPUT ;
    USE SIGNAL ;
    PORT
      LAYER M5 ;
        RECT  180.384 0 180.408 0.084 ;
    END
  END xs_q1[41]
  PIN xs_q1[42]
    DIRECTION INPUT ;
    USE SIGNAL ;
    PORT
      LAYER M5 ;
        RECT  180.48 0 180.504 0.084 ;
    END
  END xs_q1[42]
  PIN xs_q1[43]
    DIRECTION INPUT ;
    USE SIGNAL ;
    PORT
      LAYER M5 ;
        RECT  180.576 0 180.6 0.084 ;
    END
  END xs_q1[43]
  PIN xs_q1[44]
    DIRECTION INPUT ;
    USE SIGNAL ;
    PORT
      LAYER M5 ;
        RECT  180.672 0 180.696 0.084 ;
    END
  END xs_q1[44]
  PIN xs_q1[45]
    DIRECTION INPUT ;
    USE SIGNAL ;
    PORT
      LAYER M5 ;
        RECT  180.768 0 180.792 0.084 ;
    END
  END xs_q1[45]
  PIN xs_q1[46]
    DIRECTION INPUT ;
    USE SIGNAL ;
    PORT
      LAYER M5 ;
        RECT  180.864 0 180.888 0.084 ;
    END
  END xs_q1[46]
  PIN xs_q1[47]
    DIRECTION INPUT ;
    USE SIGNAL ;
    PORT
      LAYER M5 ;
        RECT  180.96 0 180.984 0.084 ;
    END
  END xs_q1[47]
  PIN xs_q1[48]
    DIRECTION INPUT ;
    USE SIGNAL ;
    PORT
      LAYER M5 ;
        RECT  181.056 0 181.08 0.084 ;
    END
  END xs_q1[48]
  PIN xs_q1[49]
    DIRECTION INPUT ;
    USE SIGNAL ;
    PORT
      LAYER M5 ;
        RECT  181.152 0 181.176 0.084 ;
    END
  END xs_q1[49]
  PIN xs_q1[4]
    DIRECTION INPUT ;
    USE SIGNAL ;
    PORT
      LAYER M5 ;
        RECT  176.832 0 176.856 0.084 ;
    END
  END xs_q1[4]
  PIN xs_q1[50]
    DIRECTION INPUT ;
    USE SIGNAL ;
    PORT
      LAYER M5 ;
        RECT  181.248 0 181.272 0.084 ;
    END
  END xs_q1[50]
  PIN xs_q1[51]
    DIRECTION INPUT ;
    USE SIGNAL ;
    PORT
      LAYER M5 ;
        RECT  181.344 0 181.368 0.084 ;
    END
  END xs_q1[51]
  PIN xs_q1[52]
    DIRECTION INPUT ;
    USE SIGNAL ;
    PORT
      LAYER M5 ;
        RECT  181.44 0 181.464 0.084 ;
    END
  END xs_q1[52]
  PIN xs_q1[53]
    DIRECTION INPUT ;
    USE SIGNAL ;
    PORT
      LAYER M5 ;
        RECT  181.536 0 181.56 0.084 ;
    END
  END xs_q1[53]
  PIN xs_q1[54]
    DIRECTION INPUT ;
    USE SIGNAL ;
    PORT
      LAYER M5 ;
        RECT  181.632 0 181.656 0.084 ;
    END
  END xs_q1[54]
  PIN xs_q1[55]
    DIRECTION INPUT ;
    USE SIGNAL ;
    PORT
      LAYER M5 ;
        RECT  181.728 0 181.752 0.084 ;
    END
  END xs_q1[55]
  PIN xs_q1[56]
    DIRECTION INPUT ;
    USE SIGNAL ;
    PORT
      LAYER M5 ;
        RECT  181.824 0 181.848 0.084 ;
    END
  END xs_q1[56]
  PIN xs_q1[57]
    DIRECTION INPUT ;
    USE SIGNAL ;
    PORT
      LAYER M5 ;
        RECT  181.92 0 181.944 0.084 ;
    END
  END xs_q1[57]
  PIN xs_q1[58]
    DIRECTION INPUT ;
    USE SIGNAL ;
    PORT
      LAYER M5 ;
        RECT  182.016 0 182.04 0.084 ;
    END
  END xs_q1[58]
  PIN xs_q1[59]
    DIRECTION INPUT ;
    USE SIGNAL ;
    PORT
      LAYER M5 ;
        RECT  182.112 0 182.136 0.084 ;
    END
  END xs_q1[59]
  PIN xs_q1[5]
    DIRECTION INPUT ;
    USE SIGNAL ;
    PORT
      LAYER M5 ;
        RECT  176.928 0 176.952 0.084 ;
    END
  END xs_q1[5]
  PIN xs_q1[60]
    DIRECTION INPUT ;
    USE SIGNAL ;
    PORT
      LAYER M5 ;
        RECT  182.208 0 182.232 0.084 ;
    END
  END xs_q1[60]
  PIN xs_q1[61]
    DIRECTION INPUT ;
    USE SIGNAL ;
    PORT
      LAYER M5 ;
        RECT  182.304 0 182.328 0.084 ;
    END
  END xs_q1[61]
  PIN xs_q1[62]
    DIRECTION INPUT ;
    USE SIGNAL ;
    PORT
      LAYER M5 ;
        RECT  182.4 0 182.424 0.084 ;
    END
  END xs_q1[62]
  PIN xs_q1[63]
    DIRECTION INPUT ;
    USE SIGNAL ;
    PORT
      LAYER M5 ;
        RECT  182.496 0 182.52 0.084 ;
    END
  END xs_q1[63]
  PIN xs_q1[64]
    DIRECTION INPUT ;
    USE SIGNAL ;
    PORT
      LAYER M5 ;
        RECT  182.592 0 182.616 0.084 ;
    END
  END xs_q1[64]
  PIN xs_q1[65]
    DIRECTION INPUT ;
    USE SIGNAL ;
    PORT
      LAYER M5 ;
        RECT  182.688 0 182.712 0.084 ;
    END
  END xs_q1[65]
  PIN xs_q1[66]
    DIRECTION INPUT ;
    USE SIGNAL ;
    PORT
      LAYER M5 ;
        RECT  182.784 0 182.808 0.084 ;
    END
  END xs_q1[66]
  PIN xs_q1[67]
    DIRECTION INPUT ;
    USE SIGNAL ;
    PORT
      LAYER M5 ;
        RECT  182.88 0 182.904 0.084 ;
    END
  END xs_q1[67]
  PIN xs_q1[68]
    DIRECTION INPUT ;
    USE SIGNAL ;
    PORT
      LAYER M5 ;
        RECT  182.976 0 183 0.084 ;
    END
  END xs_q1[68]
  PIN xs_q1[69]
    DIRECTION INPUT ;
    USE SIGNAL ;
    PORT
      LAYER M5 ;
        RECT  183.072 0 183.096 0.084 ;
    END
  END xs_q1[69]
  PIN xs_q1[6]
    DIRECTION INPUT ;
    USE SIGNAL ;
    PORT
      LAYER M5 ;
        RECT  177.024 0 177.048 0.084 ;
    END
  END xs_q1[6]
  PIN xs_q1[70]
    DIRECTION INPUT ;
    USE SIGNAL ;
    PORT
      LAYER M5 ;
        RECT  183.168 0 183.192 0.084 ;
    END
  END xs_q1[70]
  PIN xs_q1[71]
    DIRECTION INPUT ;
    USE SIGNAL ;
    PORT
      LAYER M5 ;
        RECT  183.264 0 183.288 0.084 ;
    END
  END xs_q1[71]
  PIN xs_q1[72]
    DIRECTION INPUT ;
    USE SIGNAL ;
    PORT
      LAYER M5 ;
        RECT  183.36 0 183.384 0.084 ;
    END
  END xs_q1[72]
  PIN xs_q1[73]
    DIRECTION INPUT ;
    USE SIGNAL ;
    PORT
      LAYER M5 ;
        RECT  183.456 0 183.48 0.084 ;
    END
  END xs_q1[73]
  PIN xs_q1[74]
    DIRECTION INPUT ;
    USE SIGNAL ;
    PORT
      LAYER M5 ;
        RECT  183.552 0 183.576 0.084 ;
    END
  END xs_q1[74]
  PIN xs_q1[75]
    DIRECTION INPUT ;
    USE SIGNAL ;
    PORT
      LAYER M5 ;
        RECT  183.648 0 183.672 0.084 ;
    END
  END xs_q1[75]
  PIN xs_q1[76]
    DIRECTION INPUT ;
    USE SIGNAL ;
    PORT
      LAYER M5 ;
        RECT  183.744 0 183.768 0.084 ;
    END
  END xs_q1[76]
  PIN xs_q1[77]
    DIRECTION INPUT ;
    USE SIGNAL ;
    PORT
      LAYER M5 ;
        RECT  183.84 0 183.864 0.084 ;
    END
  END xs_q1[77]
  PIN xs_q1[78]
    DIRECTION INPUT ;
    USE SIGNAL ;
    PORT
      LAYER M5 ;
        RECT  183.936 0 183.96 0.084 ;
    END
  END xs_q1[78]
  PIN xs_q1[79]
    DIRECTION INPUT ;
    USE SIGNAL ;
    PORT
      LAYER M5 ;
        RECT  184.032 0 184.056 0.084 ;
    END
  END xs_q1[79]
  PIN xs_q1[7]
    DIRECTION INPUT ;
    USE SIGNAL ;
    PORT
      LAYER M5 ;
        RECT  177.12 0 177.144 0.084 ;
    END
  END xs_q1[7]
  PIN xs_q1[80]
    DIRECTION INPUT ;
    USE SIGNAL ;
    PORT
      LAYER M5 ;
        RECT  184.128 0 184.152 0.084 ;
    END
  END xs_q1[80]
  PIN xs_q1[81]
    DIRECTION INPUT ;
    USE SIGNAL ;
    PORT
      LAYER M5 ;
        RECT  184.224 0 184.248 0.084 ;
    END
  END xs_q1[81]
  PIN xs_q1[82]
    DIRECTION INPUT ;
    USE SIGNAL ;
    PORT
      LAYER M5 ;
        RECT  184.32 0 184.344 0.084 ;
    END
  END xs_q1[82]
  PIN xs_q1[83]
    DIRECTION INPUT ;
    USE SIGNAL ;
    PORT
      LAYER M5 ;
        RECT  184.416 0 184.44 0.084 ;
    END
  END xs_q1[83]
  PIN xs_q1[84]
    DIRECTION INPUT ;
    USE SIGNAL ;
    PORT
      LAYER M5 ;
        RECT  184.512 0 184.536 0.084 ;
    END
  END xs_q1[84]
  PIN xs_q1[85]
    DIRECTION INPUT ;
    USE SIGNAL ;
    PORT
      LAYER M5 ;
        RECT  184.608 0 184.632 0.084 ;
    END
  END xs_q1[85]
  PIN xs_q1[86]
    DIRECTION INPUT ;
    USE SIGNAL ;
    PORT
      LAYER M5 ;
        RECT  184.704 0 184.728 0.084 ;
    END
  END xs_q1[86]
  PIN xs_q1[87]
    DIRECTION INPUT ;
    USE SIGNAL ;
    PORT
      LAYER M5 ;
        RECT  184.8 0 184.824 0.084 ;
    END
  END xs_q1[87]
  PIN xs_q1[88]
    DIRECTION INPUT ;
    USE SIGNAL ;
    PORT
      LAYER M5 ;
        RECT  184.896 0 184.92 0.084 ;
    END
  END xs_q1[88]
  PIN xs_q1[89]
    DIRECTION INPUT ;
    USE SIGNAL ;
    PORT
      LAYER M5 ;
        RECT  184.992 0 185.016 0.084 ;
    END
  END xs_q1[89]
  PIN xs_q1[8]
    DIRECTION INPUT ;
    USE SIGNAL ;
    PORT
      LAYER M5 ;
        RECT  177.216 0 177.24 0.084 ;
    END
  END xs_q1[8]
  PIN xs_q1[90]
    DIRECTION INPUT ;
    USE SIGNAL ;
    PORT
      LAYER M5 ;
        RECT  185.088 0 185.112 0.084 ;
    END
  END xs_q1[90]
  PIN xs_q1[91]
    DIRECTION INPUT ;
    USE SIGNAL ;
    PORT
      LAYER M5 ;
        RECT  185.184 0 185.208 0.084 ;
    END
  END xs_q1[91]
  PIN xs_q1[92]
    DIRECTION INPUT ;
    USE SIGNAL ;
    PORT
      LAYER M5 ;
        RECT  185.28 0 185.304 0.084 ;
    END
  END xs_q1[92]
  PIN xs_q1[93]
    DIRECTION INPUT ;
    USE SIGNAL ;
    PORT
      LAYER M5 ;
        RECT  185.376 0 185.4 0.084 ;
    END
  END xs_q1[93]
  PIN xs_q1[94]
    DIRECTION INPUT ;
    USE SIGNAL ;
    PORT
      LAYER M5 ;
        RECT  185.472 0 185.496 0.084 ;
    END
  END xs_q1[94]
  PIN xs_q1[95]
    DIRECTION INPUT ;
    USE SIGNAL ;
    PORT
      LAYER M5 ;
        RECT  185.568 0 185.592 0.084 ;
    END
  END xs_q1[95]
  PIN xs_q1[96]
    DIRECTION INPUT ;
    USE SIGNAL ;
    PORT
      LAYER M5 ;
        RECT  185.664 0 185.688 0.084 ;
    END
  END xs_q1[96]
  PIN xs_q1[97]
    DIRECTION INPUT ;
    USE SIGNAL ;
    PORT
      LAYER M5 ;
        RECT  185.76 0 185.784 0.084 ;
    END
  END xs_q1[97]
  PIN xs_q1[98]
    DIRECTION INPUT ;
    USE SIGNAL ;
    PORT
      LAYER M5 ;
        RECT  185.856 0 185.88 0.084 ;
    END
  END xs_q1[98]
  PIN xs_q1[99]
    DIRECTION INPUT ;
    USE SIGNAL ;
    PORT
      LAYER M5 ;
        RECT  185.952 0 185.976 0.084 ;
    END
  END xs_q1[99]
  PIN xs_q1[9]
    DIRECTION INPUT ;
    USE SIGNAL ;
    PORT
      LAYER M5 ;
        RECT  177.312 0 177.336 0.084 ;
    END
  END xs_q1[9]
  PIN xs_v
    DIRECTION INPUT ;
    USE SIGNAL ;
    PORT
      LAYER M5 ;
        RECT  201.216 0 201.24 0.084 ;
    END
  END xs_v
  PIN VSS
    DIRECTION INOUT ;
    USE GROUND ;
    PORT
      LAYER M5 ;
        RECT  261.204 4.297 261.324 217.103 ;
        RECT  256.884 4.297 257.004 217.103 ;
        RECT  252.564 4.297 252.684 217.103 ;
        RECT  248.244 4.297 248.364 217.103 ;
        RECT  243.924 4.297 244.044 217.103 ;
        RECT  239.604 4.297 239.724 217.103 ;
        RECT  235.284 4.297 235.404 217.103 ;
        RECT  230.964 4.297 231.084 217.103 ;
        RECT  226.644 4.297 226.764 217.103 ;
        RECT  222.324 4.297 222.444 217.103 ;
        RECT  218.004 4.297 218.124 217.103 ;
        RECT  213.684 4.297 213.804 217.103 ;
        RECT  209.364 4.297 209.484 217.103 ;
        RECT  205.044 4.297 205.164 217.103 ;
        RECT  200.724 4.297 200.844 217.103 ;
        RECT  196.404 4.297 196.524 217.103 ;
        RECT  192.084 4.297 192.204 217.103 ;
        RECT  187.764 4.297 187.884 217.103 ;
        RECT  183.444 4.297 183.564 217.103 ;
        RECT  179.124 4.297 179.244 217.103 ;
        RECT  174.804 4.297 174.924 217.103 ;
        RECT  170.484 4.297 170.604 217.103 ;
        RECT  166.164 4.297 166.284 217.103 ;
        RECT  161.844 4.297 161.964 217.103 ;
        RECT  157.524 4.297 157.644 217.103 ;
        RECT  153.204 4.297 153.324 217.103 ;
        RECT  148.884 4.297 149.004 217.103 ;
        RECT  144.564 4.297 144.684 217.103 ;
        RECT  140.244 4.297 140.364 217.103 ;
        RECT  135.924 4.297 136.044 217.103 ;
        RECT  131.604 4.297 131.724 217.103 ;
        RECT  127.284 4.297 127.404 217.103 ;
        RECT  122.964 4.297 123.084 217.103 ;
        RECT  118.644 4.297 118.764 217.103 ;
        RECT  114.324 4.297 114.444 217.103 ;
        RECT  110.004 4.297 110.124 217.103 ;
        RECT  105.684 4.297 105.804 217.103 ;
        RECT  101.364 4.297 101.484 217.103 ;
        RECT  97.044 4.297 97.164 217.103 ;
        RECT  92.724 4.297 92.844 217.103 ;
        RECT  88.404 4.297 88.524 217.103 ;
        RECT  84.084 4.297 84.204 217.103 ;
        RECT  79.764 4.297 79.884 217.103 ;
        RECT  75.444 4.297 75.564 217.103 ;
        RECT  71.124 4.297 71.244 217.103 ;
        RECT  66.804 4.297 66.924 217.103 ;
        RECT  62.484 4.297 62.604 217.103 ;
        RECT  58.164 4.297 58.284 217.103 ;
        RECT  53.844 4.297 53.964 217.103 ;
        RECT  49.524 4.297 49.644 217.103 ;
        RECT  45.204 4.297 45.324 217.103 ;
        RECT  40.884 4.297 41.004 217.103 ;
        RECT  36.564 4.297 36.684 217.103 ;
        RECT  32.244 4.297 32.364 217.103 ;
        RECT  27.924 4.297 28.044 217.103 ;
        RECT  23.604 4.297 23.724 217.103 ;
        RECT  19.284 4.297 19.404 217.103 ;
        RECT  14.964 4.297 15.084 217.103 ;
        RECT  10.644 4.297 10.764 217.103 ;
        RECT  6.324 4.297 6.444 217.103 ;
    END
  END VSS
  PIN VDD
    DIRECTION INOUT ;
    USE POWER ;
    PORT
      LAYER M5 ;
        RECT  261.396 4.311 261.516 217.089 ;
        RECT  257.076 4.311 257.196 217.089 ;
        RECT  252.756 4.311 252.876 217.089 ;
        RECT  248.436 4.311 248.556 217.089 ;
        RECT  244.116 4.311 244.236 217.089 ;
        RECT  239.796 4.311 239.916 217.089 ;
        RECT  235.476 4.311 235.596 217.089 ;
        RECT  231.156 4.311 231.276 217.089 ;
        RECT  226.836 4.311 226.956 217.089 ;
        RECT  222.516 4.311 222.636 217.089 ;
        RECT  218.196 4.311 218.316 217.089 ;
        RECT  213.876 4.311 213.996 217.089 ;
        RECT  209.556 4.311 209.676 217.089 ;
        RECT  205.236 4.311 205.356 217.089 ;
        RECT  200.916 4.311 201.036 217.089 ;
        RECT  196.596 4.311 196.716 217.089 ;
        RECT  192.276 4.311 192.396 217.089 ;
        RECT  187.956 4.311 188.076 217.089 ;
        RECT  183.636 4.311 183.756 217.089 ;
        RECT  179.316 4.311 179.436 217.089 ;
        RECT  174.996 4.311 175.116 217.089 ;
        RECT  170.676 4.311 170.796 217.089 ;
        RECT  166.356 4.311 166.476 217.089 ;
        RECT  162.036 4.311 162.156 217.089 ;
        RECT  157.716 4.311 157.836 217.089 ;
        RECT  153.396 4.311 153.516 217.089 ;
        RECT  149.076 4.311 149.196 217.089 ;
        RECT  144.756 4.311 144.876 217.089 ;
        RECT  140.436 4.311 140.556 217.089 ;
        RECT  136.116 4.311 136.236 217.089 ;
        RECT  131.796 4.311 131.916 217.089 ;
        RECT  127.476 4.311 127.596 217.089 ;
        RECT  123.156 4.311 123.276 217.089 ;
        RECT  118.836 4.311 118.956 217.089 ;
        RECT  114.516 4.311 114.636 217.089 ;
        RECT  110.196 4.311 110.316 217.089 ;
        RECT  105.876 4.311 105.996 217.089 ;
        RECT  101.556 4.311 101.676 217.089 ;
        RECT  97.236 4.311 97.356 217.089 ;
        RECT  92.916 4.311 93.036 217.089 ;
        RECT  88.596 4.311 88.716 217.089 ;
        RECT  84.276 4.311 84.396 217.089 ;
        RECT  79.956 4.311 80.076 217.089 ;
        RECT  75.636 4.311 75.756 217.089 ;
        RECT  71.316 4.311 71.436 217.089 ;
        RECT  66.996 4.311 67.116 217.089 ;
        RECT  62.676 4.311 62.796 217.089 ;
        RECT  58.356 4.311 58.476 217.089 ;
        RECT  54.036 4.311 54.156 217.089 ;
        RECT  49.716 4.311 49.836 217.089 ;
        RECT  45.396 4.311 45.516 217.089 ;
        RECT  41.076 4.311 41.196 217.089 ;
        RECT  36.756 4.311 36.876 217.089 ;
        RECT  32.436 4.311 32.556 217.089 ;
        RECT  28.116 4.311 28.236 217.089 ;
        RECT  23.796 4.311 23.916 217.089 ;
        RECT  19.476 4.311 19.596 217.089 ;
        RECT  15.156 4.311 15.276 217.089 ;
        RECT  10.836 4.311 10.956 217.089 ;
        RECT  6.516 4.311 6.636 217.089 ;
    END
  END VDD
  OBS
    LAYER RVTN ;
     RECT  4.32 0 264.06 221.4 ;
    LAYER RVTP ;
     RECT  4.32 0 264.06 221.4 ;
    LAYER M1 ;
     RECT  4.32 0 264.06 221.4 ;
    LAYER M2 ;
     RECT  4.32 0 264.06 221.4 ;
    LAYER M3 ;
     RECT  4.32 0 264.06 221.4 ;
    LAYER M4 ;
     RECT  4.32 0 264.06 221.4 ;
    LAYER M5 ;
     RECT  4.32 0 264.06 221.4 ;
  END
END ot_v41_rom_elem_q_qxpq_w10_gb_hw
END LIBRARY
